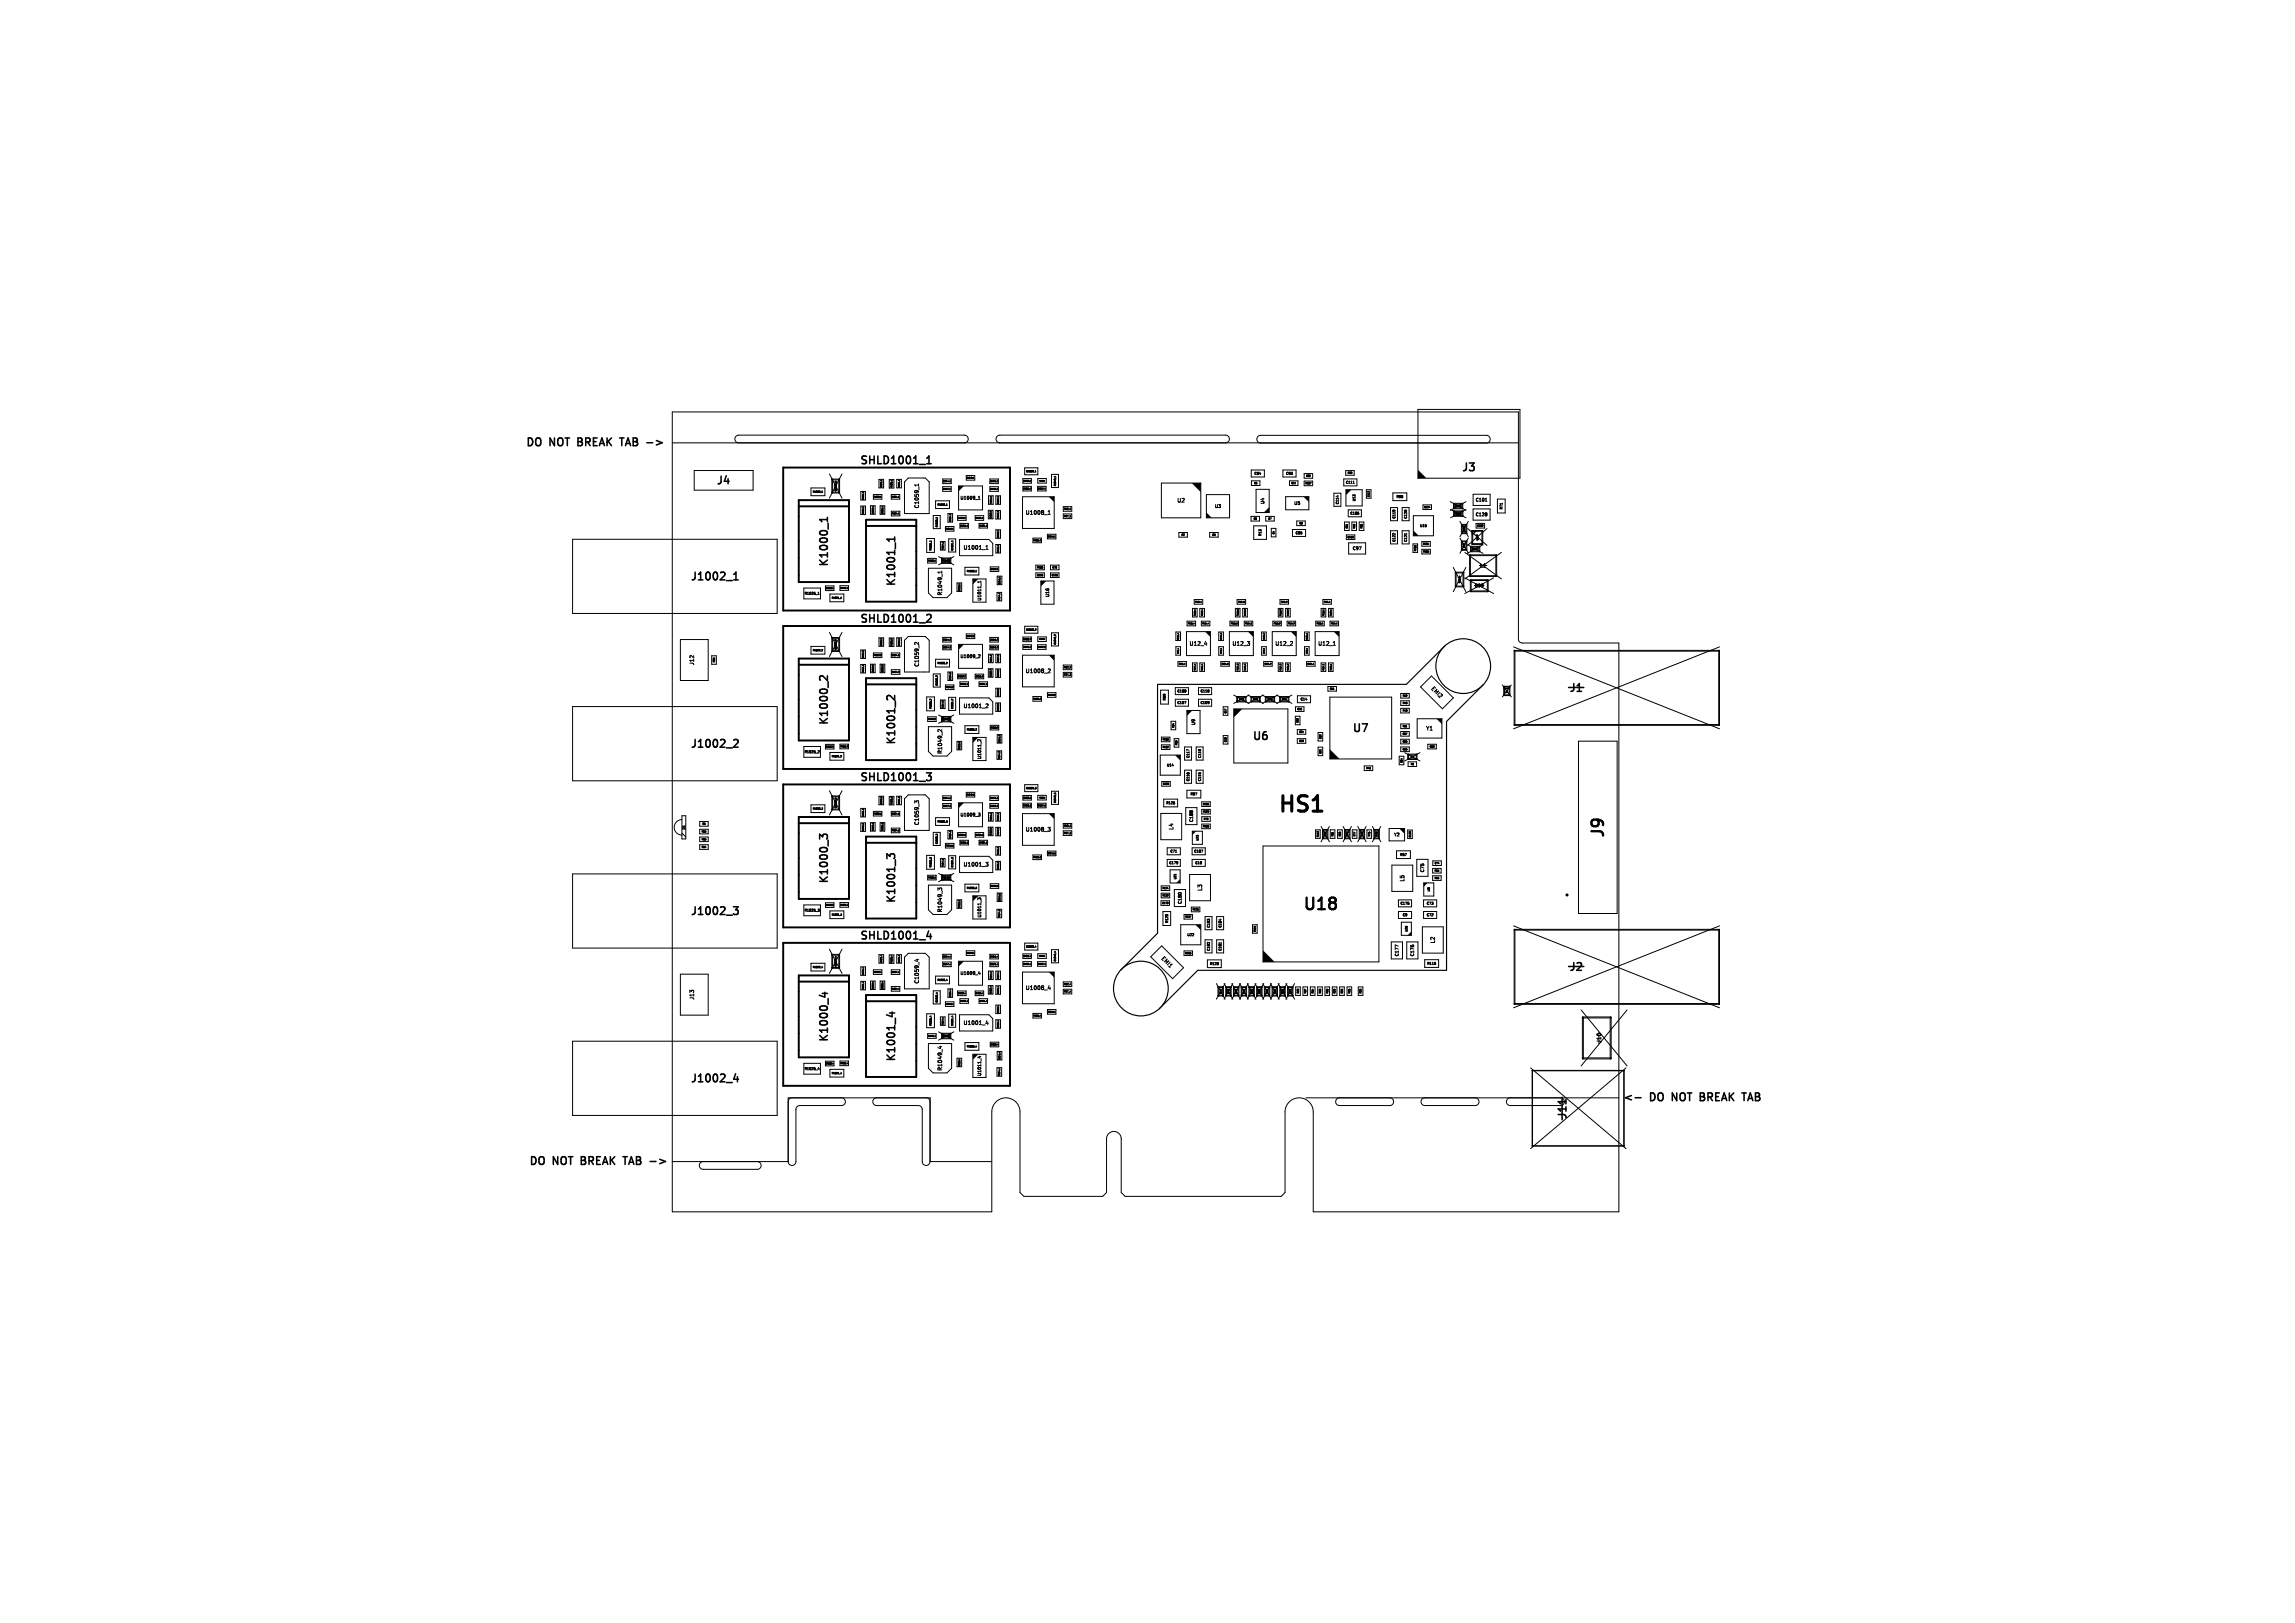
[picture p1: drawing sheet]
<svg xmlns="http://www.w3.org/2000/svg" width="297mm" height="210mm" viewBox="0 0 297 210" stroke-linecap="round" stroke-linejoin="round" font-family="sans-serif">
<defs><g id="words">
<text font-size="2.8" x="165.1" y="105.7">HS1</text>
<g font-size="2.1">
<text x="208" y="108.6" transform="rotate(-90 208 108.6)">J9</text>
<text x="168.4" y="118.2">U18</text>
</g>
<g font-size="1.4">
<text x="68" y="57.8">DO</text>
<text x="71.2" y="57.8">NOT</text>
<text x="75.2" y="57.8">BREAK TAB -&gt;</text>
<text x="92.6" y="63">J4</text>
<text x="111.2" y="60.4">SHLD1001_1</text>
<text x="189" y="61.3">J3</text>
<text x="89.2" y="75.4">J1002_1</text>
<text x="107.4" y="73.5" transform="rotate(-90 107.4 73.5)">K1000_1</text>
<text x="116.1" y="76" transform="rotate(-90 116.1 76)">K1001_1</text>
<text x="111.2" y="80.9">SHLD1001_2</text>
<text x="202.9" y="89.8">J1</text>
<text x="107.4" y="94" transform="rotate(-90 107.4 94)">K1000_2</text>
<text x="174.9" y="95">U7</text>
<text x="89.2" y="97">J1002_2</text>
<text x="111.2" y="101.4">SHLD1001_3</text>
<text x="116.1" y="96.5" transform="rotate(-90 116.1 96.5)">K1001_2</text>
<text x="162" y="96">U6</text>
<text x="89.2" y="118.7">J1002_3</text>
<text x="107.4" y="114.5" transform="rotate(-90 107.4 114.5)">K1000_3</text>
<text x="116.1" y="117" transform="rotate(-90 116.1 117)">K1001_3</text>
<text x="111.2" y="121.9">SHLD1001_4</text>
<text x="202.9" y="125.9">J2</text>
<text x="107.4" y="135" transform="rotate(-90 107.4 135)">K1000_4</text>
<text x="116.1" y="137.5" transform="rotate(-90 116.1 137.5)">K1001_4</text>
<text x="89.2" y="140.3">J1002_4</text>
<text x="210" y="142.6">&lt;-</text>
<text x="213.6" y="142.6">DO</text>
<text x="216.8" y="142.6">NOT</text>
<text x="220.9" y="142.6">BREAK TAB</text>
<text x="203" y="144.9" transform="rotate(-90 203 144.9)">J11</text>
<text x="68.3" y="150.8">DO</text>
<text x="71.5" y="150.8">NOT</text>
<text x="75.5" y="150.8">BREAK TAB -&gt;</text>
</g>
<g font-size=".7">
<text x="119.1" y="65.9" transform="rotate(-90 119.1 65.9)">C1059_1</text>
<text x="152.2" y="65.2">U2</text>
<text x="124.6" y="71.3">U1001_1</text>
<text x="132.6" y="66.7">U1008_1</text>
<text x="122.1" y="77.2" transform="rotate(-90 122.1 77.2)">R1049_1</text>
<text x="191.4" y="73.6">L1</text>
<text x="153.8" y="83.7">U12_4</text>
<text x="159.4" y="83.7">U12_3</text>
<text x="164.9" y="83.7">U12_2</text>
<text x="170.5" y="83.7">U12_1</text>
<text x="90" y="86.2" transform="rotate(-90 90 86.2)">J12</text>
<text x="119.1" y="86.4" transform="rotate(-90 119.1 86.4)">C1059_2</text>
<text x="132.6" y="87.2">U1008_2</text>
<text x="185" y="89.2" transform="rotate(45 185 89.2)">EMI2</text>
<text x="124.6" y="91.8">U1001_2</text>
<text x="184.4" y="94.7">Y1</text>
<text x="122.1" y="97.7" transform="rotate(-90 122.1 97.7)">R1049_2</text>
<text x="119.1" y="106.9" transform="rotate(-90 119.1 106.9)">C1059_3</text>
<text x="132.6" y="107.7">U1008_3</text>
<text x="152" y="107.5" transform="rotate(-90 152 107.5)">L4</text>
<text x="124.6" y="112.3">U1001_3</text>
<text x="122.1" y="118.2" transform="rotate(-90 122.1 118.2)">R1049_3</text>
<text x="155.7" y="115.4" transform="rotate(-90 155.7 115.4)">L3</text>
<text x="181.9" y="114.2" transform="rotate(-90 181.9 114.2)">L5</text>
<text x="150.1" y="124.1" transform="rotate(45 150.1 124.1)">EMI1</text>
<text x="185.8" y="122.2" transform="rotate(-90 185.8 122.2)">L2</text>
<text x="90" y="129.5" transform="rotate(-90 90 129.5)">J13</text>
<text x="119.1" y="127.4" transform="rotate(-90 119.1 127.4)">C1059_4</text>
<text x="132.6" y="128.2">U1008_4</text>
<text x="124.6" y="132.8">U1001_4</text>
<text x="207.3" y="135.1" transform="rotate(-90 207.3 135.1)">J10</text>
<text x="122.1" y="138.7" transform="rotate(-90 122.1 138.7)">R1049_4</text>
</g>
<g font-size=".6">
<text x="124.2" y="64.7">U1009_1</text>
<text x="157.1" y="65.8">U3</text>
<text x="163.7" y="65.3" transform="rotate(-90 163.7 65.3)">U4</text>
<text x="167.4" y="65.4">U5</text>
<text x="190.9" y="65">C101</text>
<text x="175" y="71.3">C97</text>
<text x="190.9" y="66.9">C128</text>
<text x="127.1" y="77.8" transform="rotate(-90 127.1 77.8)">U1011_1</text>
<text x="135.9" y="77.3" transform="rotate(-90 135.9 77.3)">U16</text>
<text x="190.8" y="76.1">C99</text>
<text x="124.2" y="85.2">U1009_2</text>
<text x="154.8" y="93.9" transform="rotate(-90 154.8 93.9)">U9</text>
<text x="127.1" y="98.3" transform="rotate(-90 127.1 98.3)">U1011_2</text>
<text x="124.2" y="105.7">U1009_3</text>
<text x="154.5" y="106.5" transform="rotate(-90 154.5 106.5)">C188</text>
<text x="180.3" y="108.3">Y2</text>
<text x="184.4" y="113" transform="rotate(-90 184.4 113)">C75</text>
<text x="127.1" y="118.8" transform="rotate(-90 127.1 118.8)">U1011_3</text>
<text x="153" y="117.1" transform="rotate(-90 153 117.1)">C180</text>
<text x="181.1" y="123.8" transform="rotate(-90 181.1 123.8)">C177</text>
<text x="183.1" y="123.8" transform="rotate(-90 183.1 123.8)">C176</text>
<text x="124.2" y="126.2">U1009_4</text>
<text x="127.1" y="139.3" transform="rotate(-90 127.1 139.3)">U1011_4</text>
</g>
<g font-size=".4">
<text x="162.3" y="61.5">C94</text>
<text x="166.4" y="61.5">C93</text>
<text x="173.3" y="65.3" transform="rotate(-90 173.3 65.3)">C114</text>
<text x="174.1" y="62.7">C111</text>
<text x="175.5" y="64.9" transform="rotate(-90 175.5 64.9)">U13</text>
<text x="180.7" y="64.5">R98</text>
<text x="194.5" y="66" transform="rotate(-90 194.5 66)">R71</text>
<text x="163.3" y="69.4" transform="rotate(-90 163.3 69.4)">R13</text>
<text x="167.6" y="69.2">C85</text>
<text x="174.7" y="66.7">C106</text>
<text x="180.6" y="70.2" transform="rotate(-90 180.6 70.2)">C122</text>
<text x="180.6" y="67.2" transform="rotate(-90 180.6 67.2)">C119</text>
<text x="182.1" y="70.2" transform="rotate(-90 182.1 70.2)">C121</text>
<text x="182.1" y="67.2" transform="rotate(-90 182.1 67.2)">C120</text>
<text x="183.7" y="68.3">U15</text>
<text x="104.1" y="77">R1025_1</text>
<text x="189.1" y="75.5" transform="rotate(-90 189.1 75.5)">R14</text>
<text x="152.3" y="89.7">C108</text>
<text x="155.3" y="89.7">C110</text>
<text x="150.9" y="90.7" transform="rotate(-90 150.9 90.7)">R89</text>
<text x="152.3" y="91.2">C107</text>
<text x="155.3" y="91.2">C109</text>
<text x="168.3" y="90.7">C14</text>
<text x="104.1" y="97.5">R1025_2</text>
<text x="150.9" y="99.2">U14</text>
<text x="154" y="101.1" transform="rotate(-90 154 101.1)">C116</text>
<text x="154" y="98.1" transform="rotate(-90 154 98.1)">C117</text>
<text x="155.5" y="101.1" transform="rotate(-90 155.5 101.1)">C115</text>
<text x="155.5" y="98.1" transform="rotate(-90 155.5 98.1)">C118</text>
<text x="88.7" y="107.4" transform="rotate(-90 88.7 107.4)">D1</text>
<text x="150.9" y="104.1">R126</text>
<text x="154" y="103">R97</text>
<text x="151.3" y="111.9">C179</text>
<text x="151.4" y="110.4">C71</text>
<text x="154.5" y="110.4">C187</text>
<text x="154.6" y="111.9">C10</text>
<text x="181.1" y="110.8">R57</text>
<text x="104.1" y="118">R1025_3</text>
<text x="151.2" y="119.5" transform="rotate(-90 151.2 119.5)">R120</text>
<text x="181.2" y="117.1">C175</text>
<text x="181.5" y="118.6">C9</text>
<text x="184.6" y="117.1">C73</text>
<text x="184.6" y="118.6">C72</text>
<text x="153.6" y="121.2">U22</text>
<text x="156.5" y="124.9">R123</text>
<text x="156.6" y="123.1" transform="rotate(-90 156.6 123.1)">C182</text>
<text x="156.6" y="120.1" transform="rotate(-90 156.6 120.1)">C183</text>
<text x="158.1" y="123.1" transform="rotate(-90 158.1 123.1)">C181</text>
<text x="158.1" y="120.1" transform="rotate(-90 158.1 120.1)">C184</text>
<text x="184.6" y="124.9">R116</text>
<text x="104.1" y="138.5">R1025_4</text>
</g>
<g font-size=".3">
<text x="105.2" y="63.8">R1022_1</text>
<text x="108.3" y="63.6" transform="rotate(-90 108.3 63.6)">C1022_1</text>
<text x="121.3" y="65.5">R1038_1</text>
<text x="132.8" y="61.1">C1039_1</text>
<text x="136.7" y="62.9" transform="rotate(-90 136.7 62.9)">C1040_1</text>
<text x="162.3" y="62.7">C5</text>
<text x="167.1" y="62.7">C11</text>
<text x="168.9" y="62.7">R107</text>
<text x="169" y="61.7">C82</text>
<text x="174.4" y="61.4">R90</text>
<text x="177.3" y="64.3" transform="rotate(-90 177.3 64.3)">C112</text>
<text x="184.3" y="65.8">C124</text>
<text x="188.3" y="65.6">C100</text>
<text x="120.6" y="71.3" transform="rotate(-90 120.6 71.3)">R1035_1</text>
<text x="121.4" y="68.2" transform="rotate(-90 121.4 68.2)">C1030_1</text>
<text x="123.4" y="71.3" transform="rotate(-90 123.4 71.3)">C1031_1</text>
<text x="137.6" y="67">R97_1</text>
<text x="137.6" y="66">R52_1</text>
<text x="152.9" y="69.4">C2</text>
<text x="156.9" y="69.4">C3</text>
<text x="162.2" y="67.3">C6</text>
<text x="164.1" y="67.3">C7</text>
<text x="165" y="69.2" transform="rotate(-90 165 69.2)">C4</text>
<text x="168.1" y="67.9">C8</text>
<text x="174.4" y="69.7">C103</text>
<text x="174.5" y="68.4" transform="rotate(-90 174.5 68.4)">R91</text>
<text x="175.4" y="68.4" transform="rotate(-90 175.4 68.4)">R93</text>
<text x="176.4" y="68.4" transform="rotate(-90 176.4 68.4)">R96</text>
<text x="183.3" y="71.4" transform="rotate(-90 183.3 71.4)">R100</text>
<text x="184.1" y="70.5">R104</text>
<text x="184.1" y="71.5">R105</text>
<text x="188.3" y="66.6">R109</text>
<text x="189.6" y="70.9" transform="rotate(-90 189.6 70.9)">R72</text>
<text x="189.6" y="68.9" transform="rotate(-90 189.6 68.9)">R110</text>
<text x="190.5" y="71.2">C127</text>
<text x="191.2" y="68.2">C102</text>
<text x="191.4" y="70" transform="rotate(-90 191.4 70)">U17</text>
<text x="107.6" y="77.5">R1021_1</text>
<text x="125.1" y="74.1">R1003_1</text>
<text x="134.2" y="74.6">C125</text>
<text x="134.2" y="73.6">R106</text>
<text x="136.1" y="74.6">C126</text>
<text x="136.2" y="73.6">C76</text>
<text x="132.8" y="81.6">C1039_2</text>
<text x="136.7" y="83.4" transform="rotate(-90 136.7 83.4)">C1040_2</text>
<text x="92.6" y="85.7" transform="rotate(-90 92.6 85.7)">R83</text>
<text x="105.2" y="84.3">R1022_2</text>
<text x="108.3" y="84.1" transform="rotate(-90 108.3 84.1)">C1022_2</text>
<text x="121.3" y="86">R1038_2</text>
<text x="121.4" y="88.7" transform="rotate(-90 121.4 88.7)">C1030_2</text>
<text x="137.6" y="86.5">R52_2</text>
<text x="137.6" y="87.5">R97_2</text>
<text x="172.1" y="89.3">C51</text>
<text x="120.6" y="91.8" transform="rotate(-90 120.6 91.8)">R1035_2</text>
<text x="123.4" y="91.8" transform="rotate(-90 123.4 91.8)">C1031_2</text>
<text x="125.1" y="94.6">R1003_2</text>
<text x="150.4" y="95.8">R103</text>
<text x="152" y="94.2" transform="rotate(-90 152 94.2)">R94</text>
<text x="158.8" y="92.3" transform="rotate(-90 158.8 92.3)">C17</text>
<text x="160.3" y="90.6">R18</text>
<text x="162.2" y="90.6">R19</text>
<text x="164" y="90.6">R20</text>
<text x="165.9" y="90.6">R21</text>
<text x="167.9" y="91.9">C16</text>
<text x="168.1" y="93.6" transform="rotate(-90 168.1 93.6)">R22</text>
<text x="168.1" y="94.9">C24</text>
<text x="171" y="95.7" transform="rotate(-90 171 95.7)">C62</text>
<text x="181.5" y="94.1">R51</text>
<text x="181.5" y="95.1">C67</text>
<text x="181.5" y="91.1">R49</text>
<text x="181.5" y="92.1">R48</text>
<text x="181.5" y="90.2">R52</text>
<text x="107.6" y="98">R1021_2</text>
<text x="150.4" y="96.8">R102</text>
<text x="150.5" y="101.6">C123</text>
<text x="152.4" y="96.5" transform="rotate(-90 152.4 96.5)">R99</text>
<text x="158.8" y="96.1" transform="rotate(-90 158.8 96.1)">C18</text>
<text x="168.1" y="96">C19</text>
<text x="171" y="97.6" transform="rotate(-90 171 97.6)">C91</text>
<text x="176.8" y="99.6">R43</text>
<text x="181.5" y="96.1">C66</text>
<text x="181.5" y="97.1">C65</text>
<text x="181.5" y="98.7" transform="rotate(-90 181.5 98.7)">C64</text>
<text x="182.5" y="98.1">R4</text>
<text x="182.5" y="99">R5</text>
<text x="185" y="96.8">C68</text>
<text x="90.8" y="107.8">R65</text>
<text x="90.9" y="106.8">R6</text>
<text x="105.2" y="104.8">R1022_3</text>
<text x="108.3" y="104.6" transform="rotate(-90 108.3 104.6)">C1022_3</text>
<text x="121.3" y="106.5">R1038_3</text>
<text x="132.8" y="102.1">C1039_3</text>
<text x="136.7" y="103.9" transform="rotate(-90 136.7 103.9)">C1040_3</text>
<text x="137.6" y="108">R97_3</text>
<text x="137.6" y="107">R52_3</text>
<text x="155.7" y="105.2">R129</text>
<text x="155.7" y="104.2">C186</text>
<text x="155.7" y="107.1">R130</text>
<text x="155.7" y="106.1">R70</text>
<text x="90.8" y="108.8">R85</text>
<text x="90.8" y="109.8">R64</text>
<text x="120.6" y="112.3" transform="rotate(-90 120.6 112.3)">R1035_3</text>
<text x="121.4" y="109.2" transform="rotate(-90 121.4 109.2)">C1030_3</text>
<text x="123.4" y="112.3" transform="rotate(-90 123.4 112.3)">C1031_3</text>
<text x="152.3" y="113.8" transform="rotate(-90 152.3 113.8)">U21</text>
<text x="155.2" y="108.8" transform="rotate(-90 155.2 108.8)">U23</text>
<text x="170.7" y="108.4" transform="rotate(-90 170.7 108.4)">R112</text>
<text x="171.7" y="108.3" transform="rotate(-90 171.7 108.3)">R82</text>
<text x="172.6" y="108.3" transform="rotate(-90 172.6 108.3)">R81</text>
<text x="173.6" y="108.3" transform="rotate(-90 173.6 108.3)">R80</text>
<text x="174.5" y="108.3" transform="rotate(-90 174.5 108.3)">R79</text>
<text x="175.5" y="108.3" transform="rotate(-90 175.5 108.3)">R77</text>
<text x="176.4" y="108.3" transform="rotate(-90 176.4 108.3)">R78</text>
<text x="177.4" y="108.3" transform="rotate(-90 177.4 108.3)">R76</text>
<text x="178.3" y="108.3" transform="rotate(-90 178.3 108.3)">R75</text>
<text x="182.6" y="108.4" transform="rotate(-90 182.6 108.4)">C130</text>
<text x="185.6" y="112.8">R55</text>
<text x="185.6" y="113.8">R56</text>
<text x="185.6" y="111.9">C74</text>
<text x="107.6" y="118.5">R1021_3</text>
<text x="125.1" y="115.1">R1003_3</text>
<text x="150.4" y="117">C178</text>
<text x="150.4" y="116">R122</text>
<text x="150.4" y="115.1">R124</text>
<text x="153.4" y="118.8">R127</text>
<text x="154.3" y="117.8">R125</text>
<text x="185.1" y="115.4" transform="rotate(-90 185.1 115.4)">U8</text>
<text x="105.2" y="125.3">R1022_4</text>
<text x="108.3" y="125.1" transform="rotate(-90 108.3 125.1)">C1022_4</text>
<text x="132.8" y="122.6">C1039_4</text>
<text x="136.7" y="124.4" transform="rotate(-90 136.7 124.4)">C1040_4</text>
<text x="153.4" y="123.5">C185</text>
<text x="162.6" y="120.6" transform="rotate(-90 162.6 120.6)">R115</text>
<text x="182.2" y="120.6" transform="rotate(-90 182.2 120.6)">U20</text>
<text x="121.3" y="127">R1038_4</text>
<text x="121.4" y="129.7" transform="rotate(-90 121.4 129.7)">C1030_4</text>
<text x="137.6" y="127.5">R52_4</text>
<text x="137.6" y="128.5">R97_4</text>
<text x="158.1" y="128.6" transform="rotate(-90 158.1 128.6)">C47</text>
<text x="159.1" y="128.6" transform="rotate(-90 159.1 128.6)">C46</text>
<text x="160.1" y="128.6" transform="rotate(-90 160.1 128.6)">C43</text>
<text x="161.1" y="128.6" transform="rotate(-90 161.1 128.6)">C42</text>
<text x="162.1" y="128.6" transform="rotate(-90 162.1 128.6)">C39</text>
<text x="163.1" y="128.6" transform="rotate(-90 163.1 128.6)">C38</text>
<text x="164.1" y="128.6" transform="rotate(-90 164.1 128.6)">C35</text>
<text x="165.1" y="128.6" transform="rotate(-90 165.1 128.6)">C34</text>
<text x="166.1" y="128.6" transform="rotate(-90 166.1 128.6)">C31</text>
<text x="167.1" y="128.6" transform="rotate(-90 167.1 128.6)">C30</text>
<text x="168.1" y="128.6" transform="rotate(-90 168.1 128.6)">R38</text>
<text x="169.1" y="128.6" transform="rotate(-90 169.1 128.6)">R37</text>
<text x="170" y="128.6" transform="rotate(-90 170 128.6)">R34</text>
<text x="171" y="128.6" transform="rotate(-90 171 128.6)">R33</text>
<text x="171.9" y="128.6" transform="rotate(-90 171.9 128.6)">R30</text>
<text x="172.9" y="128.6" transform="rotate(-90 172.9 128.6)">R29</text>
<text x="173.8" y="128.6" transform="rotate(-90 173.8 128.6)">R26</text>
<text x="174.8" y="128.6" transform="rotate(-90 174.8 128.6)">R25</text>
<text x="176.2" y="128.6" transform="rotate(-90 176.2 128.6)">R23</text>
<text x="120.6" y="132.8" transform="rotate(-90 120.6 132.8)">R1035_4</text>
<text x="123.4" y="132.8" transform="rotate(-90 123.4 132.8)">C1031_4</text>
<text x="125.1" y="135.6">R1003_4</text>
<text x="107.6" y="139">R1021_4</text>
</g>
<g font-size=".2">
<text x="111.8" y="64.7" transform="rotate(-90 111.8 64.7)">C1011_1</text>
<text x="113.1" y="64.4">R1002_1</text>
<text x="114.2" y="63.1" transform="rotate(-90 114.2 63.1)">C1025_1</text>
<text x="115.4" y="64.4">C1024_1</text>
<text x="115.5" y="63.1" transform="rotate(-90 115.5 63.1)">R1026_1</text>
<text x="116.5" y="63.1" transform="rotate(-90 116.5 63.1)">C1021_1</text>
<text x="122" y="62.4">C1044_1</text>
<text x="122" y="63.4">C1047_1</text>
<text x="125.1" y="61.9">C1048_1</text>
<text x="128.1" y="62.4">C1046_1</text>
<text x="128.1" y="63.4">C1049_1</text>
<text x="128.3" y="65.2" transform="rotate(-90 128.3 65.2)">R1041_1</text>
<text x="129.3" y="65.2" transform="rotate(-90 129.3 65.2)">R1037_1</text>
<text x="132.4" y="62.3">C1038_1</text>
<text x="132.4" y="63.3">C1036_1</text>
<text x="134.3" y="63.3">C1037_1</text>
<text x="111.8" y="66.5" transform="rotate(-90 111.8 66.5)">R1001_1</text>
<text x="113.1" y="66.5" transform="rotate(-90 113.1 66.5)">C1012_1</text>
<text x="114.3" y="66.5" transform="rotate(-90 114.3 66.5)">C1023_1</text>
<text x="115.4" y="66.6">R1024_1</text>
<text x="122.1" y="71.1" transform="rotate(-90 122.1 71.1)">R1047_1</text>
<text x="122.4" y="68.5">R1043_1</text>
<text x="123.1" y="67.5" transform="rotate(-90 123.1 67.5)">C1034_1</text>
<text x="124" y="67.1">C1052_1</text>
<text x="124.3" y="68.1">C1055_1</text>
<text x="126.2" y="67.1">C1056_1</text>
<text x="126.7" y="68.1">C1001_1</text>
<text x="128.3" y="67.1" transform="rotate(-90 128.3 67.1)">C1032_1</text>
<text x="129.3" y="71.5" transform="rotate(-90 129.3 71.5)">C1035_1</text>
<text x="129.3" y="69.6" transform="rotate(-90 129.3 69.6)">C1002_1</text>
<text x="129.3" y="67.1" transform="rotate(-90 129.3 67.1)">R1042_1</text>
<text x="133.7" y="70">R1033_1</text>
<text x="135.6" y="69.5">C1043_1</text>
<text x="106.9" y="76.2">C1058_1</text>
<text x="108.7" y="76.2">R1053_1</text>
<text x="120.1" y="72.7">R1039_1</text>
<text x="121.9" y="72.7">R1048_1</text>
<text x="124.3" y="76.5" transform="rotate(-90 124.3 76.5)">C1053_1</text>
<text x="128.2" y="73.8">C1050_1</text>
<text x="129.4" y="77.7" transform="rotate(-90 129.4 77.7)">R1044_1</text>
<text x="129.5" y="75.6" transform="rotate(-90 129.5 75.6)">C1045_1</text>
<text x="154.6" y="78">R131_4</text>
<text x="160.2" y="78">R131_3</text>
<text x="165.7" y="78">R131_2</text>
<text x="171.3" y="78">R131_1</text>
<text x="114.2" y="83.6" transform="rotate(-90 114.2 83.6)">C1025_2</text>
<text x="115.5" y="83.6" transform="rotate(-90 115.5 83.6)">R1026_2</text>
<text x="116.5" y="83.6" transform="rotate(-90 116.5 83.6)">C1021_2</text>
<text x="122" y="82.9">C1044_2</text>
<text x="122" y="83.9">C1047_2</text>
<text x="125.1" y="82.4">C1048_2</text>
<text x="128.1" y="83.9">C1049_2</text>
<text x="128.1" y="82.9">C1046_2</text>
<text x="132.4" y="82.8">C1038_2</text>
<text x="132.4" y="83.8">C1036_2</text>
<text x="134.3" y="83.8">C1037_2</text>
<text x="152.6" y="82.8" transform="rotate(-90 152.6 82.8)">C105_4</text>
<text x="153.7" y="80.8">R135_4</text>
<text x="154.7" y="79.7" transform="rotate(-90 154.7 79.7)">R133_4</text>
<text x="155.6" y="80.8">R134_4</text>
<text x="155.7" y="79.7" transform="rotate(-90 155.7 79.7)">R132_4</text>
<text x="158.1" y="82.8" transform="rotate(-90 158.1 82.8)">C105_3</text>
<text x="159.3" y="80.8">R135_3</text>
<text x="160.3" y="79.7" transform="rotate(-90 160.3 79.7)">R133_3</text>
<text x="161.1" y="80.8">R134_3</text>
<text x="161.2" y="79.7" transform="rotate(-90 161.2 79.7)">R132_3</text>
<text x="163.7" y="82.8" transform="rotate(-90 163.7 82.8)">C105_2</text>
<text x="164.8" y="80.8">R135_2</text>
<text x="165.8" y="79.7" transform="rotate(-90 165.8 79.7)">R133_2</text>
<text x="166.7" y="80.8">R134_2</text>
<text x="166.8" y="79.7" transform="rotate(-90 166.8 79.7)">R132_2</text>
<text x="169.2" y="82.8" transform="rotate(-90 169.2 82.8)">C105_1</text>
<text x="170.4" y="80.8">R135_1</text>
<text x="171.4" y="79.7" transform="rotate(-90 171.4 79.7)">R133_1</text>
<text x="172.2" y="80.8">R134_1</text>
<text x="172.3" y="79.7" transform="rotate(-90 172.3 79.7)">R132_1</text>
<text x="111.8" y="87" transform="rotate(-90 111.8 87)">R1001_2</text>
<text x="111.8" y="85.2" transform="rotate(-90 111.8 85.2)">C1011_2</text>
<text x="113.1" y="84.9">R1002_2</text>
<text x="113.1" y="87" transform="rotate(-90 113.1 87)">C1012_2</text>
<text x="114.3" y="87" transform="rotate(-90 114.3 87)">C1023_2</text>
<text x="115.4" y="84.9">C1024_2</text>
<text x="115.4" y="87.1">R1024_2</text>
<text x="122.4" y="89">R1043_2</text>
<text x="123.1" y="88" transform="rotate(-90 123.1 88)">C1034_2</text>
<text x="124" y="87.6">C1052_2</text>
<text x="124.3" y="88.6">C1055_2</text>
<text x="126.2" y="87.6">C1056_2</text>
<text x="126.7" y="88.6">C1001_2</text>
<text x="128.3" y="87.6" transform="rotate(-90 128.3 87.6)">C1032_2</text>
<text x="128.3" y="85.7" transform="rotate(-90 128.3 85.7)">R1041_2</text>
<text x="129.3" y="87.6" transform="rotate(-90 129.3 87.6)">R1042_2</text>
<text x="129.3" y="85.7" transform="rotate(-90 129.3 85.7)">R1037_2</text>
<text x="152.5" y="86">C104_4</text>
<text x="152.6" y="84.6" transform="rotate(-90 152.6 84.6)">C70_4</text>
<text x="154.7" y="86.8" transform="rotate(-90 154.7 86.8)">R137_4</text>
<text x="155.7" y="86.8" transform="rotate(-90 155.7 86.8)">R136_4</text>
<text x="158.1" y="86">C104_3</text>
<text x="158.1" y="84.6" transform="rotate(-90 158.1 84.6)">C70_3</text>
<text x="160.3" y="86.8" transform="rotate(-90 160.3 86.8)">R137_3</text>
<text x="161.2" y="86.8" transform="rotate(-90 161.2 86.8)">R136_3</text>
<text x="163.6" y="86">C104_2</text>
<text x="163.7" y="84.6" transform="rotate(-90 163.7 84.6)">C70_2</text>
<text x="165.8" y="86.8" transform="rotate(-90 165.8 86.8)">R137_2</text>
<text x="166.8" y="86.8" transform="rotate(-90 166.8 86.8)">R136_2</text>
<text x="169.2" y="86">C104_1</text>
<text x="169.2" y="84.6" transform="rotate(-90 169.2 84.6)">C70_1</text>
<text x="171.4" y="86.8" transform="rotate(-90 171.4 86.8)">R137_1</text>
<text x="172.3" y="86.8" transform="rotate(-90 172.3 86.8)">R136_1</text>
<text x="195.1" y="89.7" transform="rotate(-90 195.1 89.7)">D2</text>
<text x="120.1" y="93.2">R1039_2</text>
<text x="121.9" y="93.2">R1048_2</text>
<text x="122.1" y="91.6" transform="rotate(-90 122.1 91.6)">R1047_2</text>
<text x="128.2" y="94.3">C1050_2</text>
<text x="129.3" y="92" transform="rotate(-90 129.3 92)">C1035_2</text>
<text x="129.3" y="90.1" transform="rotate(-90 129.3 90.1)">C1002_2</text>
<text x="133.7" y="90.5">R1033_2</text>
<text x="135.6" y="90">C1043_2</text>
<text x="106.9" y="96.7">C1058_2</text>
<text x="108.7" y="96.7">R1053_2</text>
<text x="124.3" y="97" transform="rotate(-90 124.3 97)">C1053_2</text>
<text x="129.4" y="98.2" transform="rotate(-90 129.4 98.2)">R1044_2</text>
<text x="129.5" y="96.1" transform="rotate(-90 129.5 96.1)">C1045_2</text>
<text x="111.8" y="107.5" transform="rotate(-90 111.8 107.5)">R1001_3</text>
<text x="111.8" y="105.7" transform="rotate(-90 111.8 105.7)">C1011_3</text>
<text x="113.1" y="105.4">R1002_3</text>
<text x="113.1" y="107.5" transform="rotate(-90 113.1 107.5)">C1012_3</text>
<text x="114.2" y="104.1" transform="rotate(-90 114.2 104.1)">C1025_3</text>
<text x="114.3" y="107.5" transform="rotate(-90 114.3 107.5)">C1023_3</text>
<text x="115.4" y="105.4">C1024_3</text>
<text x="115.4" y="107.6">R1024_3</text>
<text x="115.5" y="104.1" transform="rotate(-90 115.5 104.1)">R1026_3</text>
<text x="116.5" y="104.1" transform="rotate(-90 116.5 104.1)">C1021_3</text>
<text x="122" y="104.4">C1047_3</text>
<text x="122" y="103.4">C1044_3</text>
<text x="125.1" y="102.9">C1048_3</text>
<text x="128.1" y="104.4">C1049_3</text>
<text x="128.1" y="103.4">C1046_3</text>
<text x="128.3" y="106.2" transform="rotate(-90 128.3 106.2)">R1041_3</text>
<text x="129.3" y="106.2" transform="rotate(-90 129.3 106.2)">R1037_3</text>
<text x="132.4" y="103.3">C1038_3</text>
<text x="132.4" y="104.3">C1036_3</text>
<text x="134.3" y="104.3">C1037_3</text>
<text x="120.1" y="113.7">R1039_3</text>
<text x="121.9" y="113.7">R1048_3</text>
<text x="122.1" y="112.1" transform="rotate(-90 122.1 112.1)">R1047_3</text>
<text x="122.4" y="109.5">R1043_3</text>
<text x="123.1" y="108.5" transform="rotate(-90 123.1 108.5)">C1034_3</text>
<text x="124" y="108.1">C1052_3</text>
<text x="124.3" y="109.1">C1055_3</text>
<text x="126.2" y="108.1">C1056_3</text>
<text x="126.7" y="109.1">C1001_3</text>
<text x="128.3" y="108.1" transform="rotate(-90 128.3 108.1)">C1032_3</text>
<text x="129.3" y="112.5" transform="rotate(-90 129.3 112.5)">C1035_3</text>
<text x="129.3" y="110.6" transform="rotate(-90 129.3 110.6)">C1002_3</text>
<text x="129.3" y="108.1" transform="rotate(-90 129.3 108.1)">R1042_3</text>
<text x="133.7" y="111">R1033_3</text>
<text x="135.6" y="110.5">C1043_3</text>
<text x="106.9" y="117.2">C1058_3</text>
<text x="108.7" y="117.2">R1053_3</text>
<text x="124.3" y="117.5" transform="rotate(-90 124.3 117.5)">C1053_3</text>
<text x="128.2" y="114.8">C1050_3</text>
<text x="129.4" y="118.7" transform="rotate(-90 129.4 118.7)">R1044_3</text>
<text x="129.5" y="116.6" transform="rotate(-90 129.5 116.6)">C1045_3</text>
<text x="113.1" y="125.9">R1002_4</text>
<text x="114.2" y="124.6" transform="rotate(-90 114.2 124.6)">C1025_4</text>
<text x="115.4" y="125.9">C1024_4</text>
<text x="115.5" y="124.6" transform="rotate(-90 115.5 124.6)">R1026_4</text>
<text x="116.5" y="124.6" transform="rotate(-90 116.5 124.6)">C1021_4</text>
<text x="122" y="123.9">C1044_4</text>
<text x="122" y="124.9">C1047_4</text>
<text x="125.1" y="123.4">C1048_4</text>
<text x="128.1" y="123.9">C1046_4</text>
<text x="128.1" y="124.9">C1049_4</text>
<text x="132.4" y="123.8">C1038_4</text>
<text x="132.4" y="124.8">C1036_4</text>
<text x="134.3" y="124.8">C1037_4</text>
<text x="111.8" y="128" transform="rotate(-90 111.8 128)">R1001_4</text>
<text x="111.8" y="126.2" transform="rotate(-90 111.8 126.2)">C1011_4</text>
<text x="113.1" y="128" transform="rotate(-90 113.1 128)">C1012_4</text>
<text x="114.3" y="128" transform="rotate(-90 114.3 128)">C1023_4</text>
<text x="115.4" y="128.1">R1024_4</text>
<text x="122.4" y="130">R1043_4</text>
<text x="123.1" y="129" transform="rotate(-90 123.1 129)">C1034_4</text>
<text x="124" y="128.6">C1052_4</text>
<text x="124.3" y="129.6">C1055_4</text>
<text x="126.2" y="128.6">C1056_4</text>
<text x="126.7" y="129.6">C1001_4</text>
<text x="128.3" y="128.6" transform="rotate(-90 128.3 128.6)">C1032_4</text>
<text x="128.3" y="126.7" transform="rotate(-90 128.3 126.7)">R1041_4</text>
<text x="129.3" y="131.1" transform="rotate(-90 129.3 131.1)">C1002_4</text>
<text x="129.3" y="128.6" transform="rotate(-90 129.3 128.6)">R1042_4</text>
<text x="129.3" y="126.7" transform="rotate(-90 129.3 126.7)">R1037_4</text>
<text x="133.7" y="131.5">R1033_4</text>
<text x="135.6" y="131">C1043_4</text>
<text x="106.9" y="137.7">C1058_4</text>
<text x="108.7" y="137.7">R1053_4</text>
<text x="120.1" y="134.2">R1039_4</text>
<text x="121.9" y="134.2">R1048_4</text>
<text x="122.1" y="132.6" transform="rotate(-90 122.1 132.6)">R1047_4</text>
<text x="124.3" y="138" transform="rotate(-90 124.3 138)">C1053_4</text>
<text x="128.2" y="135.3">C1050_4</text>
<text x="129.3" y="133" transform="rotate(-90 129.3 133)">C1035_4</text>
<text x="129.5" y="137.1" transform="rotate(-90 129.5 137.1)">C1045_4</text>
<text x="129.4" y="139.2" transform="rotate(-90 129.4 139.2)">R1044_4</text>
</g>
</g></defs>
<g fill="none" stroke="#000" stroke-width=".13">
<path d="M87 53.3h109.5v29.4a.5 .5 0 0 0 .5 .5h12.5v73.6h-39.5v-12.9a1.82 1.82 0 0 0-1.9-1.8 1.82 1.82 0 0 0-1.8 1.8v10.4l-.5 .5h-20.2l-.5-.5v-6.9a.95 .95 0 0 0-.9-1 .95 .95 0 0 0-1 1v6.9l-.5 .5h-10.2l-.5-.5v-10.4a1.82 1.82 0 0 0-1.8-1.8 1.82 1.82 0 0 0-1.8 1.8v12.9h-41.4zM87 57.3h109.5M95.6 57.3a.5 .5 0 0 1-.5-.5 .5 .5 0 0 1 .5-.5h29.2a.5 .5 0 0 1 .5 .5 .5 .5 0 0 1-.5 .5M129.4 57.3a.5 .5 0 0 1-.5-.5 .5 .5 0 0 1 .5-.5h29.2a.5 .5 0 0 1 .5 .5 .5 .5 0 0 1-.5 .5M162.8 56.5l.4-.2h29.2a.5 .5 0 0 1 .5 .5 .5 .5 0 0 1-.6 .5h-29.1a.5 .5 0 0 1-.5-.3 .5 .5 0 0 1 .1-.5zM183.5 53h13.2v8.9h-13.2zM74.1 69.8h26.5v9.6h-26.5zM89.8 60.9h7.7v2.5h-7.7zM104 76.1h2.2v1.4h-2.2zM105 63.1h1.8v1h-1.8zM105.9 76.7v-.1v.3M105.9 76.9h.1"/>
<path d="M106.4 63.7h.1M106.4 63.6h.1M106.4 63.6v.1M106.8 75.8h1.1v.6h-1.1zM107.3 61.3l1.7 3.2M107.4 76.9h1.8v1h-1.8zM107.7 62h.1l-.1 1.8zM107.7 62h1l-1 .1zM107.7 63.7h1l-1 .1zM107.8 76.2h.1M107.8 76.1h.1M107.8 76.1v.1"/>
<path d="M108.1 62.4h.1M108.2 62.2v1.4M108.2 62.3l-.1 .1M108.2 62.3v.1M108.6 62h.1l-.1 1.8zM108.7 75.8h1.1v.6h-1.1zM108.8 77.5h.1M108.8 77.3h.1M108.8 77.3l.1 .2M109 61.3l-1.7 3.2M109.6 76.2h.1M109.6 76v.1"/>
<path d="M109.7 76v.2M109.7 76h-.1M111.4 65.5h.6v1.1h-.6zM111.4 63.6h.6v1.1h-.6zM111.7 63.8h.1M111.7 65.6v.1M111.8 63.7v.1M111.8 65.6v.1M111.8 63.7l-.1 .1M111.8 65.6h-.1M112.7 65.4h.6v1.1h-.6zM112.9 65.6h.1"/>
<path d="M113 65.5v.1M113 64h1.1v.6h-1.1zM113.8 62h.6v1.1h-.6zM113.9 65.4h.6v1.1h-.6zM114 64.4h.1M114 64.2h.1M114 64.2v.2M114.1 62.1v.1M114.1 62.2h-.1M114.3 65.5v.1M114.3 65.6h-.1M115.1 62.1h.6v1.1h-.6z"/>
<path d="M115.3 62.2h.1M115.3 64h1.1v.6h-1.1zM115.4 66.2h1.1v.6h-1.1zM115.4 62.1v.1M115.4 62.2h-.1M116.1 62h.6v1.1h-.6zM116.3 64.4h.1M116.3 66.5h.1M116.3 64.2h.1M116.3 66.4v.1M116.3 66.4h.1M116.3 64.2v.2"/>
<path d="M116.4 62.2h-.1M116.4 62.1v.1M117.6 61.9h2.2l.5 .5v4.1h-3.2v-4.1zM118.9 62.6v.3M118.9 62.8h-.5l.1 .1M119.9 69.7h1v1.8h-1zM120.1 72.3h1.1v.6h-1.1zM120.2 73.5h3v3.2l-.6 .6h-1.8l-.6-.6zM120.3 70l.1 .1M120.4 70.1h.1M120.5 70h-.2M120.5 70v.1"/>
<path d="M120.8 66.7h.9v1.7h-.9zM121 72.6h.1M121 72.5h.1M121 72.5v.1M121.1 64.8h1.8v1h-1.8zM121.1 67h.2M121.1 67h.1M121.1 67l.1 .1M121.3 66.9v.2M121.5 72l1.9 1.1M121.7 70.1h.6v1.1h-.6zM121.9 72.2h.1l-.1 .7z"/>
<path d="M121.9 72.2l1.2 .1h-1.2zM121.9 72.8l1.2 .1h-1.2zM121.9 73.9v.3M121.9 74h-.5l.1 .2M121.9 70.2h.1M122 72.6h1M122 70.2v.1M122 63h1.1v.6h-1.1zM122 62h1.1v.6h-1.1zM122.1 70.2v.1M122.1 70.2h-.2M122.4 68.1h1.1v.6h-1.1z"/>
<path d="M122.5 65.4h.1M122.5 65.2v.2M122.5 65.2v.1M122.7 66.5h.6v1.1h-.6zM122.8 69.7h.9v1.7h-.9zM122.8 72.6h.1M122.8 72.5h.1M122.9 72.5v.1M122.9 72.5h-.1M122.9 62.3h.1M122.9 63.3h.1M122.9 66.6h.1"/>
<path d="M122.9 62.2l.1 .1M122.9 62.2h.1M122.9 63.2h.1M123 63.2v.1M123 63.2h-.1M123 72.2l.1 .1-.1 .6zM123 66.6h-.1M123 66.5v.1M123.3 68.5h.1M123.3 68.4v.1M123.3 70h-.2l.1 .1M123.3 70v.1"/>
<path d="M123.4 72l-1.9 1.1M123.9 75.4h.6v1.1h-.6zM123.9 66.7h1.1v.6h-1.1zM124.1 62.9h3.1v3.1h-3.1zM124.2 69.8h3.8l.5 .5v1.6h-4.3zM124.2 75.5v.1M124.2 75.6h-.1M124.2 67.7h1.1v.6h-1.1zM124.9 67.1h.1M124.9 67v.1M124.9 73.4h1.8v1h-1.8zM125 61.5h1.1v.6h-1.1z"/>
<path d="M125.2 68.1h.1M125.2 68h.1M125.2 68v.1M125.9 74.9h1.7v3h-1.7zM126 61.9h.1M126 61.8h.1M126 61.7v.2M126 61.7v.1M126.2 66.7h1.1v.6h-1.1zM126.3 74h.1M126.3 73.8v.1M126.3 73.8v.2"/>
<path d="M126.3 73.8h.1M126.6 64.6h.2M126.6 64.3l.1-.1v.4M126.7 67.7h1.1v.6h-1.1zM126.9 75.2v.2M126.9 75.3h-.4l.1 .1M127.1 67.1h.1M127.1 67h.1M127.2 67v.1M127.2 67h-.1M127.6 71.1h.3M127.6 70.7l.1-.1v.5"/>
<path d="M127.6 68.1h.1M127.6 68l.1 .1M127.6 68h.1M127.9 66h.6v1.1h-.6zM127.9 64.2h.6v1.1h-.6zM128.1 63h1.1v.6h-1.1zM128.1 62h1.1v.6h-1.1zM128.1 64.3h.2M128.1 64.3h.1M128.2 73.4h1.1v.6h-1.1zM128.2 66.2h.1M128.2 64.3h.1"/>
<path d="M128.3 66.1v.1M128.3 66.2h-.1M128.3 64.2v.1M128.9 64.2h.6v1.1h-.6zM128.9 68.6h.6v1.1h-.6zM128.9 70.5h.6v1.1h-.6zM128.9 66.1h.6v1.1h-.6zM129 63.2l.1 .1M129 63.3h.1M129 76.7h.6v1.1h-.6zM129 62.3h.1M129 62.2l.1 .1"/>
<path d="M129 62.2h.1M129.1 74.6h.6v1.1h-.6zM129.1 73.7h.1M129.1 73.6v.1M129.1 73.6h.1M129.1 66.2h.1M129.1 70.6h.1M129.1 68.7h.1M129.1 64.3h.1M129.2 64.2v.1M129.2 66.1v.1M129.2 68.6v.1"/>
<path d="M129.2 70.5v.1M129.2 64.3h-.1M129.2 66.2h-.1M129.2 70.6h-.1M129.2 68.7h-.1M129.4 76.7v.1M129.4 76.8h-.1M129.4 74.6v.1M129.4 74.7h-.1M132.3 64.3h4.1v4.1h-4.1zM132.4 61.9h1.1v.6h-1.1zM132.4 62.9h1.1v.6h-1.1z"/>
<path d="M132.6 60.5h1.7v.9h-1.7zM133.3 63.3h.1M133.3 63.2v.1M133.3 62.3h.1M133.3 62.2h.1M133.3 62.2v.1M133.7 69.6h1.1v.6h-1.1zM134 61.1h.1M134 60.9h.1M134 60.9v.2M134.1 73.1h1.1v.6h-1.1zM134.1 74.1h1.1v.6h-1.1z"/>
<path d="M134.3 62.9h1.1v.6h-1.1zM134.3 61.9h1.1v.6h-1.1zM134.5 62.2h.1M134.6 62.2l-.1 .1M134.6 62.2h.1M134.6 70h.1M134.6 69.9h.1M134.6 62.2v.1M134.6 69.9v.1M134.7 62.3h.1M134.7 62.2v.1M134.7 62.2h.1"/>
<path d="M134.7 75.2h1.7v3h-1.7zM134.8 62.2h.1M134.8 62.2v.1M134.8 62.3h.1M134.8 74.3h.1M134.9 62.2h.1M134.9 62.2v.1M134.9 62.3h.1M134.9 73.3h.1M134.9 74.4h.1M134.9 73.4h.1M134.9 74.5h.1"/>
<path d="M134.9 73.5h.1M134.9 73.4v.1M134.9 74.4v.1M135 62.2h.1M135 62.3h.1M135.1 62.3h.1M135.2 62.2h-.1M135.2 62.2v.1M135.2 63.3h.1M135.2 63.2h.1M135.2 63.1v.2M135.2 63.1v.1"/>
<path d="M135.6 69.1h1.1v.6h-1.1zM135.6 66.6h.3M135.6 66.2l.2-.1v.5M136 73.1h1.1v.6h-1.1zM136 74.1h1.1v.6h-1.1zM136.1 61.4h.9v1.7h-.9zM136.5 61.7h.1M136.5 69.5h.1M136.5 69.4v.1M136.6 61.6v.1M136.6 61.7h-.1M136.8 74.3h.1"/>
<path d="M136.8 74.4v.1M136.8 74.5h.1M137.6 65.6h1.1v.6h-1.1zM137.6 66.5h1.1v.6h-1.1zM138.5 66.9h.1M138.5 65.9h.1M138.5 65.8v.1M138.5 66.7v.2M150.3 62.5h5.1v4.5h-5.1zM152.6 68.9h1.1v.6h-1.1zM154.3 78.7h.6v1.1h-.6zM154.5 77.6h1.1v.6h-1.1z"/>
<path d="M154.6 78.9h.1M154.6 78.9v.1M155.3 78.7h.6v1.1h-.6zM155.4 77.9h.1M155.5 77.8v.1M155.5 78.9h.1M155.6 78.9v.1M156.1 64h3v3h-3zM156.5 68.9h1.1v.6h-1.1zM159.9 78.7h.6v1.1h-.6zM160.1 77.6h1.1v.6h-1.1zM160.1 78.9v.1"/>
<path d="M160.2 78.9h-.1M160.2 78.9h.1M160.2 78.9v.1M160.8 78.7h.6v1.1h-.6zM160.9 77.8l.1 .1M161 77.9h.1M161.1 78.9l-.1 .1M161.1 78.9h.1M161.2 78.9h.1M161.2 78.9v.1M161.9 66.8h1.1v.6h-1.1zM161.9 60.8h1.7v.9h-1.7z"/>
<path d="M162 62.2h1.1v.6h-1.1zM162.2 68h1.7v1.8h-1.7zM162.6 63.3h1.7v3h-1.7zM163.8 66.8h1.1v.6h-1.1zM164.5 68.4h.6v1.1h-.6zM165.4 78.7h.6v1.1h-.6zM165.6 78.9v.1M165.6 78.9h.1M165.6 77.6h1.1v.6h-1.1zM165.7 78.9h.1M165.7 78.9l.1 .1v-.1M166 60.8h1.7v.9h-1.7z"/>
<path d="M166.4 78.7h.6v1.1h-.6zM166.4 64.3h3v1.7h-3zM166.5 77.8h.1M166.6 77.8h.1M166.6 77.8l-.1 .1h.1M166.6 78.9v.1M166.6 78.9h.1M166.6 78.9l.1 .1v-.1M166.9 62.2h1.1v.6h-1.1zM167.3 68.5h1.7v.9h-1.7zM167.6 62.6h.1M167.8 67.4h1.1v.6h-1.1z"/>
<path d="M168.8 62.2h1.1v.6h-1.1zM168.8 61.3h1.1v.6h-1.1zM169.5 62.4h.2l-.1 .2M171 78.7h.6v1.1h-.6zM171.2 77.6h1.1v.6h-1.1zM171.3 78.9v.1M171.3 78.9l-.1 .1M171.9 78.7h.6v1.1h-.6zM172.1 77.9h.1M172.1 77.8h.1M172.1 77.8v.1M172.1 78.9h.2"/>
<path d="M172.1 78.9h.1M172.2 78.9v.1M172.3 78.9v.1M172.6 63.8h.9v1.7h-.9zM173.1 64.1v.2M173.9 62h1.7v.9h-1.7zM174 67.5h.6v1.1h-.6zM174.2 60.9h1.1v.6h-1.1zM174.2 63.4h2.1v2.1h-2.1zM174.2 69.2h1.1v.6h-1.1zM174.4 67.8v.2M174.5 66h1.7v.9h-1.7z"/>
<path d="M174.5 70.2h2.2v1.5h-2.2zM175 67.5h.6v1.1h-.6zM175 69.4h.1v.1M175.1 69.5h.1M175.1 62.6h.2M175.1 69.5v.1M175.1 69.6h.1M175.2 62.3v.3M175.8 66.3h.1M175.8 66.4h.1M175.8 66.4v.2M175.9 67.5h.6v1.1h-.6z"/>
<path d="M176.8 63.4h.6v1.1h-.6zM177 63.6h.1M177.1 63.6h-.1M177.1 63.6h.1M177.1 63.6l.1 .1v-.1M180 65.7h.9v1.7h-.9zM180 68.7h.9v1.7h-.9zM180.3 66l-.1 .1M180.3 63.8h1.8v1h-1.8zM180.3 66l.2 .1M180.3 66h.1M180.4 66h.1"/>
<path d="M180.4 66v.1M180.5 69v.2l-.1-.2-.2 .1M181.5 65.7h.9v1.7h-.9zM181.5 68.7h.9v1.7h-.9zM181.8 66h.2M182 69v.2M182 69.1h-.2M182.9 70.4h.6v1.1h-.6zM182.9 66.7h2.6v2.6h-2.6zM183.2 70.6h-.1M183.2 70.6h.1M184 71.1h1.1v.6h-1.1z"/>
<path d="M184 70.1h1.1v.6h-1.1zM184.2 65.3h1.1v.6h-1.1zM184.8 70.4h.1M184.8 71.3h.1M184.9 71.3v.1M184.9 71.4h.1M184.9 71.5h.1M184.9 71.4v.1M184.9 65.7h.2M187.7 64.9l2 1.1M187.7 65.9l2 1.1M188.1 73.4l1.6 3.2"/>
<path d="M188.1 65.1l.1 .1v.6zM188.1 65.1l1.2 .1h-1.1zM188.1 65.7l1.2 .1h-1.1zM188.1 66.1l.1 .1v.6zM188.1 66.1l1.2 .1h-1.1zM188.1 66.7l1.2 .1h-1.1zM188.3 65.5h.8M188.3 66.4h.8M188.4 74.1h1h-1zM188.4 74.1v1.8zM188.4 75.9h1h-1zM188.9 74.5v.9"/>
<path d="M188.9 67.5l1.1 1.9M188.9 69.6l1.1 2M189 65.4v.2M189 66.3v.1M189 66.4l.1 .1M189.1 66.5h-.1M189.1 66.4v.1M189.1 67.9h.1v1.2zM189.1 67.9h.7l-.6 .1zM189.1 69h.7l-.6 .1zM189.1 70l.7 .1h-.6zM189.1 70l.1 .1v1.1z"/>
<path d="M189.1 71.1l.7 .1h-.6zM189.2 65.1l.1 .1v.6zM189.2 66.1l.1 .1v.6zM189.4 74.1v1.8zM189.4 68.1h.1M189.5 68v.9M189.5 70.3v.6M189.6 74.8l3.7 2M189.6 71.5l4.7 3.4M189.7 73.4l-1.6 3.2M189.7 65.9l-2 1.1M189.7 64.9l-2 1.1"/>
<path d="M189.7 67.9h.1v1.2zM189.7 70l.1 .1v1.1zM189.9 70.5l2 1.1M189.9 68.4l2.5 2.2M190 67.5l-1.1 1.9M190 69.6l-1.1 2M190.2 71.8h.1l-.1 2.8zM190.2 71.8h3.5l-3.5 .1zM190.2 74.5h3.5l-3.5 .1zM190.3 75l.1 .1-.1 1.5zM190.3 75l2.3 .1h-2.3zM190.3 76.5h2.3l-2.3 .1z"/>
<path d="M190.3 70.7h.1v.7zM190.3 70.7h1.2l-1.1 .1zM190.3 71.3h1.2l-1.1 .1zM190.5 71h.8M190.5 68.7h1.4h-1.4zM190.5 68.7h.1l-.1 1.7zM190.5 70.4h1.4h-1.4zM190.5 68.7h.5l-.5 .5zM190.6 65.9h2.2v1.4h-2.2zM190.6 64h2.2v1.4h-2.2zM190.8 75.8h1.3M191 67.7h1.1v.6h-1.1z"/>
<path d="M191.1 70.9h.2l-.1 .2M191.2 69.1v.8M191.3 69.3l-.3-.1v.2M191.4 70.7h.1v.7zM191.5 73.2h.9M191.8 68.7h.1l-.1 1.7zM191.9 67.9h.1M191.9 70.5l-2 1.1M191.9 68l-.1 .1h.1M192.2 64.9h.2M192.3 64.5v.4M192.4 66.4h.1"/>
<path d="M192.4 66.5v.2M192.4 66.4v.1M192.4 68.4l-2.5 2.2M192.5 75l.1 .1-.1 1.5zM193.3 74.8l-3.7 2M193.6 71.8h.1l-.1 2.8zM193.8 64.6h1v1.8h-1zM194.3 71.5l-4.7 3.4M194.4 65.1v.2M74.1 91.4h26.5v9.6h-26.5zM88.1 82.8h3.5v5.3h-3.5zM92.1 84.9h.6v1.1h-.6z"/>
<path d="M104 96.6h2.2v1.4h-2.2zM105 83.6h1.8v1h-1.8zM105.9 97.1l.1 .1-.2 .2h.2M106.4 84h.1M106.4 84l.1 .1M106.5 84.1l-.2 .1h.2M106.8 96.3h1.1v.6h-1.1zM107.3 81.8l1.7 3.2M107.4 97.4h1.8v1h-1.8zM107.7 82.5h.1l-.1 1.8zM107.7 82.5h1l-1 .1zM107.7 84.2h1l-1 .1z"/>
<path d="M107.8 96.5h.1M107.8 96.5v.1M107.8 96.6l-.1 .1h.1M107.8 96.6h.1M108.1 82.8v.1M108.1 82.8h.1M108.1 82.8l.1 .1v-.1M108.2 82.7v1.4M108.6 82.5h.1l-.1 1.8zM108.7 96.3h1.1v.6h-1.1zM108.8 97.8h.1M108.9 97.8h.1"/>
<path d="M108.9 97.8l-.1 .2h.1M109 81.8l-1.7 3.2M109.6 96.5h.1M109.7 96.5h.1M109.7 96.5v.1M109.7 96.6l-.1 .1h.1M111.4 86h.6v1.1h-.6zM111.4 84.1h.6v1.1h-.6zM111.6 84.2v.1M111.6 86.1h.1M111.6 84.2h.1M111.7 84.2l.1 .1v-.1"/>
<path d="M111.7 86.1l.1 .1v-.1M112.7 85.9h.6v1.1h-.6zM112.9 86.1h.1M112.9 86v.1M112.9 86h.1M112.9 86l.1 .1v-.1M113 84.5h1.1v.6h-1.1zM113.8 82.5h.6v1.1h-.6zM113.9 85.9h.6v1.1h-.6zM114 82.7h.1M114 82.6v.1M114 82.6h.1"/>
<path d="M114 84.7h.1M114 82.6l.1 .1v-.1M114 84.8l-.1 .1h.1M114 84.7v.1M114.1 86v.1M114.1 86h.1M114.2 86h.1M114.3 86v.1l-.1-.1M115.1 82.6h.6v1.1h-.6zM115.3 82.7h.1M115.3 82.6v.1M115.3 82.6h.1"/>
<path d="M115.3 84.5h1.1v.6h-1.1zM115.3 82.6l.1 .1v-.1M115.4 86.7h1.1v.6h-1.1zM116.1 82.5h.6v1.1h-.6zM116.3 82.7h.1M116.3 82.6v.1M116.3 82.6h.1M116.3 84.7h.1M116.3 82.6l.1 .1v-.1M116.3 86.9h.1M116.3 84.8v.1h.1M116.4 84.7h.1"/>
<path d="M116.4 84.7l-.1 .1M116.4 86.9l-.1 .1h.1M116.4 86.9h.1M117.6 82.4h2.2l.5 .5v4.1h-3.2v-4.1zM118.9 83.1v.3l-.4-.3-.1 .1v.2M119.9 90.2h1v1.8h-1zM120.1 92.8h1.1v.6h-1.1zM120.2 94h3v3.2l-.6 .6h-1.8l-.6-.6zM120.3 90.5v.1M120.3 90.6h.1M120.3 90.5h.1M120.4 90.5h-.1"/>
<path d="M120.4 90.5h.1M120.5 90.5v.1l-.1-.1M120.8 87.2h.9v1.7h-.9zM121 93h.1M121.1 93h.1M121.1 93l-.1 .1h.1M121.1 85.3h1.8v1h-1.8zM121.1 87.5h.1M121.1 87.4v.1M121.2 87.4h.1M121.2 87.4h-.1M121.2 87.4l.1 .2v-.2"/>
<path d="M121.5 92.5l1.9 1.1M121.7 90.6h.6v1.1h-.6zM121.9 92.7h.1l-.1 .7zM121.9 92.7l1.2 .1h-1.2zM121.9 93.3l1.2 .1h-1.2zM121.9 94.4v.3l-.4-.3-.1 .1v.2M121.9 90.7h.1M122 93.1h1M122 82.5h1.1v.6h-1.1zM122 83.5h1.1v.6h-1.1zM122.1 90.7v.1l-.2-.1M122.4 88.6h1.1v.6h-1.1z"/>
<path d="M122.5 85.7h.1M122.6 85.7h.1M122.6 85.7v.1M122.6 85.8l-.1 .1h.1M122.7 87h.6v1.1h-.6zM122.8 90.2h.9v1.7h-.9zM122.8 93h.1M122.9 87.1h.1M122.9 93h.1M122.9 93l-.1 .1h.1M122.9 83.7h.1M122.9 82.7h.1"/>
<path d="M123 92.7l.1 .1-.1 .6zM123 82.7h.1M123 83.7h.1M123 83.7l-.1 .1h.1M123 82.7l-.1 .1h.1M123 87v.1h-.1M123.2 90.5h.1M123.2 90.5l-.1 .1M123.2 90.5l.1 .1v-.1M123.3 88.8v.1M123.3 88.8l.1 .1M123.4 88.9h.1"/>
<path d="M123.4 88.9l-.1 .1h.1M123.4 92.5l-1.9 1.1M123.9 95.9h.6v1.1h-.6zM123.9 87.2h1.1v.6h-1.1zM124.1 83.4h3.1v3.1h-3.1zM124.1 96.1h.1M124.1 96v.1M124.1 96h.1M124.1 96l.1 .1v-.1M124.2 90.3h3.8l.5 .5v1.6h-4.3zM124.2 88.2h1.1v.6h-1.1zM124.9 93.9h1.8v1h-1.8z"/>
<path d="M124.9 87.4v.1M124.9 87.5h.1M124.9 87.5l-.1 .1h.1M125 82h1.1v.6h-1.1zM125.2 88.4v.1M125.2 88.5h.1M125.2 88.5l-.1 .1h.1M125.9 95.4h1.7v3h-1.7zM126 82.2v.1M126.1 82.3l-.1 .1h.1M126.1 82.3h.1M126.2 87.2h1.1v.6h-1.1z"/>
<path d="M126.3 94.3h.1M126.4 94.3h.1M126.4 94.3v.1M126.4 94.4l-.1 .1h.1M126.6 95.7v.2M126.6 95.7h.1M126.6 84.7h.2v.1l-.2 .3h.2M126.7 88.2h1.1v.6h-1.1zM126.9 95.7v.2l-.2-.2h-.1M127.1 87.4v.1M127.1 87.4l.1 .1M127.2 87.5h.1"/>
<path d="M127.2 87.5l-.1 .1h.1M127.6 91.1h.2l.1 .1-.3 .4h.3M127.6 88.4h.1M127.6 88.4v.1M127.7 88.4v.1M127.7 88.5h.1M127.7 88.5l-.1 .1h.1M127.9 86.5h.6v1.1h-.6zM127.9 84.7h.6v1.1h-.6zM128.1 83.5h1.1v.6h-1.1zM128.1 82.5h1.1v.6h-1.1zM128.1 86.6v.1"/>
<path d="M128.1 86.6h.1M128.1 84.8h.1M128.2 93.9h1.1v.6h-1.1zM128.2 84.8h.1M128.2 86.6l.1 .1v-.1M128.2 84.7v.1M128.2 84.7h.1M128.2 84.7l.1 .1v-.1M128.9 84.7h.6v1.1h-.6zM128.9 89.1h.6v1.1h-.6zM128.9 91h.6v1.1h-.6zM128.9 86.6h.6v1.1h-.6z"/>
<path d="M129 97.2h.6v1.1h-.6zM129.1 95.1h.6v1.1h-.6zM129.1 83.7h-.1M129.1 83.7h.1M129.1 82.7h-.1M129.1 82.7h.1M129.1 86.7h.1M129.1 84.8h.1M129.1 89.2h.1M129.1 91.1h.1M129.1 94.1h.1M129.1 83.7l-.1 .1h.1"/>
<path d="M129.1 82.7l-.1 .1h.1M129.1 86.6v.1M129.1 91v.1M129.1 89.1v.1M129.1 89.1h.1M129.1 84.7h.1M129.1 84.7v.1M129.1 86.6l.1 .1v-.1M129.1 84.7l.1 .1v-.1M129.1 89.1l.1 .1v-.1M129.1 91l.1 .1v-.1M129.2 94.1h.1"/>
<path d="M129.2 94.1l-.1 .1h.1M129.2 97.3h.1M129.3 97.3h-.1M129.3 97.3h.1M129.3 95.2h.1M129.3 97.2v.1M129.3 97.2h.1M129.3 97.2l.1 .1v-.1M129.3 95.1l.1 .1v-.1M132.3 84.8h4.1v4.1h-4.1zM132.4 83.4h1.1v.6h-1.1zM132.4 82.4h1.1v.6h-1.1z"/>
<path d="M132.6 81h1.7v.9h-1.7zM133.3 83.7h.1M133.4 82.6l-.1 .1M133.4 82.6v.1M133.4 82.7h.1M133.4 82.7l-.1 .1h.1M133.4 83.7l-.1 .1h.1M133.4 83.7h.1M133.7 90.1h1.1v.6h-1.1zM134 81.4h.1M134.1 81.4h.1M134.1 81.4l-.1 .2h.1"/>
<path d="M134.3 83.4h1.1v.6h-1.1zM134.3 82.4h1.1v.6h-1.1zM134.5 82.7h.1M134.6 82.7l-.1 .1M134.6 82.7h.1M134.6 90.3v.1M134.6 90.3l.1 .1M134.6 82.7v.1M134.7 90.4h.1M134.7 90.4l-.1 .1h.1M134.7 82.8h.1M134.7 82.7h.1"/>
<path d="M134.7 82.7v.1M134.8 82.7h.1M134.8 82.7v.1M134.8 82.8h.1M134.9 82.7h.1M134.9 82.7v.1M134.9 82.8h.1M135 82.7h.1M135 82.7v.1M135 82.8h.1M135.1 82.7h.1M135.2 82.7h.1"/>
<path d="M135.2 82.7h-.1M135.2 82.7l-.1 .1M135.2 82.8h-.2M135.2 83.7h.1M135.3 83.7h.1M135.3 83.7l-.1 .1h.1M135.6 89.6h1.1v.6h-1.1zM135.7 86.6h.1l.1 .1-.3 .4h.3M136.1 81.9h.9v1.7h-.9zM136.4 82.2h.1M136.4 82.1v.1M136.5 82.1h-.1"/>
<path d="M136.5 82.1h.1M136.5 82.1l.1 .1v-.1M136.5 89.8v.1M136.5 89.9h.1M136.6 89.9h.1M136.6 89.9l-.1 .1h.1M137.6 86.1h1.1v.6h-1.1zM137.6 87h1.1v.6h-1.1zM138.5 86.2l.1 .1M138.5 87.2h.1M138.6 86.3h.1M138.6 87.2h.1"/>
<path d="M138.6 87.2l-.1 .2h.1M138.6 86.3l-.1 .1h.1M150.2 97.7h2.6v2.6h-2.6zM150.2 89.3h1v1.8h-1zM150.3 95.4h1.1v.6h-1.1zM150.3 96.4h1.1v.6h-1.1zM151.1 95.6h.1h-.1M151.2 95.6v.1M151.2 96.6h.1M151.2 95.7h.1M151.2 95.8h.1M151.2 96.7l-.1 .1h.1"/>
<path d="M151.2 95.7v.1M151.2 96.6v.1M151.6 93.3h.6v1.1h-.6zM151.7 99h.2M152 95.6h.6v1.1h-.6zM152.1 90.5h1.7v.9h-1.7zM152.1 89h1.7v.9h-1.7zM152.2 83.7h.6v1.1h-.6zM152.2 81.8h.6v1.1h-.6zM152.4 82h.1M152.4 85.6h1.1v.6h-1.1zM152.5 81.9v.1"/>
<path d="M152.5 83.9v.1M153.3 90.8h.2l-.1 .3M153.3 85.9h.1M153.3 96.7h.9v1.7h-.9zM153.3 99.7h.9v1.7h-.9zM153.4 85.9v.1M153.4 89.3h.1M153.5 89.3h.1M153.5 89.3l-.1 .2M153.5 81.7h3.1v3.1h-3.1zM153.6 91.9h1.7v3h-1.7zM153.6 80.4h1.1v.6h-1.1z"/>
<path d="M153.9 100h-.2M153.9 100h.1M153.9 97.1l-.3-.1v.2M154.3 85.8h.6v1.1h-.6zM154.5 80.7h.1M154.5 80.6v.1M154.6 86h.1M154.6 85.9v.1M154.8 96.7h.9v1.7h-.9zM154.8 99.7h.9v1.7h-.9zM155.1 100v.1M155.1 90.5h1.7v.9h-1.7z"/>
<path d="M155.1 89h1.7v.9h-1.7zM155.1 97h.1M155.2 97h.1M155.2 100h.1M155.2 100h.2M155.2 97h.2M155.3 85.8h.6v1.1h-.6zM155.4 97h.1M155.4 100h.1M155.5 80.4h1.1v.6h-1.1zM155.5 86h.1M155.6 85.9v.1"/>
<path d="M155.9 83.3h.3M156.1 83.2v.3M156.3 80.7h.1M156.4 80.6v.1M156.4 90.8h.1M156.4 89.3l.1 .2M156.4 90.9h.1M156.5 90.8v.1M156.5 89.5h-.1M156.5 90.9l-.1 .1M156.5 90.9h-.1M157.7 81.8h.6v1.1h-.6z"/>
<path d="M157.7 83.7h.6v1.1h-.6zM158 85.6h1.1v.6h-1.1zM158 82l-.1-.1v.1M158 84l-.1-.1v.1M158 82h.1M158 83.9h.1M158 81.9v.1M158 81.9h.1M158.1 83.9h.1M158.1 81.9h.1M158.1 82h.1M158.3 91.5h.6v1.1h-.6z"/>
<path d="M158.3 95.2h.6v1.1h-.6zM158.8 85.8h.1v.1M158.9 85.9h.1M158.9 86h.1M158.9 85.9v.1M159.1 81.7h3.1v3.1h-3.1zM159.2 80.4h1.1v.6h-1.1zM159.7 89.9l1.9 1.1M159.7 91.7h7v7h-7zM159.9 85.8h.6v1.1h-.6zM160 80.6l.1 .1M160 80.7h.1"/>
<path d="M160.1 90.1l.1 .1-.1 .6zM160.1 90.1l1.2 .1h-1.2zM160.1 90.7l1.2 .1h-1.2zM160.1 80.7h.1M160.1 86h.1M160.2 86h-.1M160.2 85.9v.1M160.2 86h.1M160.3 90.5h.7M160.8 85.8h.6v1.1h-.6zM161 80.4h1.1v.6h-1.1zM161.1 86h-.1"/>
<path d="M161.1 85.9h.1M161.1 85.9v.1M161.2 90.1l.1 .1-.1 .6zM161.2 85.9v.1M161.2 86h.1M161.4 83h.3l-.1 .2M161.5 89.9l2 1.1M161.6 83.2l.1 .1-.1 .2M161.6 89.9l-1.9 1.1M161.9 80.6h.1l-.1 .1M161.9 90.1l.1 .1-.1 .6zM161.9 90.1l1.2 .1h-1.2z"/>
<path d="M161.9 90.7l1.2 .1h-1.2zM161.9 80.7h.1M162 80.7h-.1M162 80.7h.1M162.2 90.5h.6M163 90.1l.1 .1-.1 .6zM163.3 83.7h.6v1.1h-.6zM163.3 81.8h.6v1.1h-.6zM163.4 89.9l1.9 1.1M163.5 89.9l-2 1.1M163.5 83.9h.1M163.5 82h.1"/>
<path d="M163.5 81.9v.1M163.5 81.9h.1M163.5 85.6h1.1v.6h-1.1zM163.6 83.9v.1v-.1M163.6 81.9v.1v-.1M163.8 90.1l.1 .1-.1 .6zM163.8 90.1l1.2 .1h-1.2zM163.8 90.7l1.2 .1h-1.2zM164 90.5h.7M164.4 85.8h.1M164.5 85.8h.1M164.5 85.8v.1"/>
<path d="M164.5 85.9l-.1 .1h.1M164.5 85.9h.1M164.6 81.7h3.1v3.1h-3.1zM164.7 80.4h1.1v.6h-1.1zM164.9 90.1l.1 .1-.1 .6zM165.2 89.9l2 1.1M165.3 89.9l-1.9 1.1M165.4 85.8h.6v1.1h-.6zM165.6 80.6h.1M165.6 90.1l.1 .1v.6zM165.6 90.1l1.2 .1h-1.1zM165.6 90.7l1.2 .1h-1.1z"/>
<path d="M165.6 86h.1M165.7 80.6l-.1 .1h.1M165.7 80.6h.1M165.7 85.9h.1M165.7 85.9l.1 .1v-.1M165.9 90.5h.6M166.3 90.6h.2M166.4 85.8h.6v1.1h-.6zM166.6 80.4h1.1v.6h-1.1zM166.6 86h.1M166.6 85.9h.1M166.6 85.9v.1"/>
<path d="M166.6 85.9l.1 .1v-.1M166.7 90.1l.1 .1v.6zM167.2 83v.2l-.2 .3h.3M167.2 89.9l-2 1.1M167.4 80.6h.1M167.5 80.6h.1M167.5 80.6l-.1 .1h.1M167.6 92.7h.6v1.1h-.6zM167.7 91.5h1.1v.6h-1.1zM167.9 94.4h1.1v.6h-1.1zM167.9 95.6h1.1v.6h-1.1zM167.9 90h1.7v.9h-1.7z"/>
<path d="M168.8 83.7h.6v1.1h-.6zM168.8 81.8h.6v1.1h-.6zM169.1 85.6h1.1v.6h-1.1zM169.2 81.9v.1M169.2 83.9v.1M169.2 84h-.1M169.2 82h-.1M169.9 86h.1M170 85.8v.1M170 85.8v.2M170 85.8h.1M170.2 81.7h3.1v3.1h-3.1z"/>
<path d="M170.3 80.4h1.1v.6h-1.1zM170.6 94.8h.6v1.1h-.6zM170.6 96.7h.6v1.1h-.6zM171 97v.1M171 85.8h.6v1.1h-.6zM171.1 80.7h.1M171.2 80.6v.1M171.2 80.6h-.1M171.2 86h.1M171.3 85.9v.1M171.3 86h-.1M171.9 88.8h1.1v.6h-1.1z"/>
<path d="M171.9 85.8h.6v1.1h-.6zM172.1 90.2h8v8h-8zM172.1 80.4h1.1v.6h-1.1zM172.1 86h.2M172.1 86h.1M172.2 86h.1M172.3 85.9v.1M172.5 83.5h.3M172.5 89.2h.2M172.6 83.1l.1-.1v.5M173 80.7h.1M173 80.6v.1"/>
<path d="M173 80.6h.1M176.6 99.1h1.1v.6h-1.1zM181.1 97.9h.6v1.1h-.6zM181.3 95.7h1.1v.6h-1.1zM181.3 96.7h1.1v.6h-1.1zM181.3 89.7h1.1v.6h-1.1zM181.3 90.7h1.1v.6h-1.1zM181.3 91.7h1.1v.6h-1.1zM181.3 93.7h1.1v.6h-1.1zM181.3 94.7h1.1v.6h-1.1zM181.8 97.4l2 1.1M182 94.1h.1"/>
<path d="M182.2 97.6h.1l-.1 .7zM182.2 97.6h1.2l-1.2 .1zM182.2 98.2h1.2l-1.2 .1zM182.2 98.6h1.1v.6h-1.1zM182.6 97.9h.4M183.3 97.6h.1l-.1 .7zM183.4 93h3.2v2.5h-3.2zM183.8 97.4l-2 1.1M184.8 96.3h1.1v.6h-1.1zM185.3 87.5l2.8 2.8-1.4 1.4-2.9-2.8zM194.4 88.6l1.2 1.6M194.6 88.8l.8 .1h-.7z"/>
<path d="M194.6 88.8l.1 .1v1.1zM194.6 89.9l.8 .1h-.7zM194.7 88.9h.7v.2h-.7zM195 89.3v.4M195.3 88.8l.1 .1v1.1zM195.6 88.6l-1.2 1.6M195.9 83.7l26.6 10.6M196 84.2h.1l-.1 9.7zM196 84.2h26.5l-26.5 .1zM196 93.8h26.5l-26.5 .1zM204.3 95.9h5v22.3h-5zM222.4 84.2h.1v9.7z"/>
<path d="M222.5 83.7l-26.6 10.6M74.1 113.1h26.5v9.6h-26.5zM88.2 105.6h.5v3h-.5zM88.2 107.8l.5 .5M88.3 106.1a1 1 0 0 0-1 1 1 1 0 0 0 1 1M90.6 106.3h1.1v.6h-1.1zM90.6 109.3h1.1v.6h-1.1zM90.6 107.3h1.1v.6h-1.1zM90.6 108.3h1.1v.6h-1.1zM104 117.1h2.2v1.4h-2.2zM105 104.1h1.8v1h-1.8zM105.8 117.6h.2l-.1 .1 .1 .2h-.1"/>
<path d="M106.3 104.5h.2l-.1 .1M106.4 104.7h.1M106.4 104.6h.1M106.5 104.6v.1M106.5 104.7h-.1M106.8 116.8h1.1v.6h-1.1zM107.3 102.3l1.7 3.2M107.4 117.9h1.8v1h-1.8zM107.7 103h.1l-.1 1.8zM107.7 103h1l-1 .1zM107.7 104.7h1l-1 .1zM107.7 117h.1v.1"/>
<path d="M107.8 117.1h.1M107.8 117.2h.1M107.8 117.1v.1M108.1 103.3h-.1v.1M108.1 103.3l.1 .1M108.1 103.3h.1M108.2 103.2v1.4M108.6 103h.1l-.1 1.8zM108.7 116.8h1.1v.6h-1.1zM108.8 118.3h.1M108.9 118.3v.1M108.9 118.4l-.1 .1"/>
<path d="M108.9 118.4h.1M109 102.3l-1.7 3.2M109.6 117h.1v.1M109.7 117.1h.1M109.7 117.2h-.1M109.7 117.1v.1M111.4 104.6h.6v1.1h-.6zM111.4 106.5h.6v1.1h-.6zM111.7 104.7h-.1v.1M111.7 106.6h-.1v.1M111.7 104.7h.1M111.7 106.6h.1"/>
<path d="M111.8 104.7v.1M111.8 106.6h.1M112.7 106.4h.6v1.1h-.6zM112.9 106.6v-.1v.1M112.9 106.6h.1M112.9 106.5v.1M113 106.5h-.1M113 106.5h.1M113 106.5v.1M113 105h1.1v.6h-1.1zM113.8 103h.6v1.1h-.6zM113.9 106.4h.6v1.1h-.6z"/>
<path d="M113.9 105.2l.1 .1M114 105.4h.1M114 105.3h.1M114 105.3v.1M114 103.1v.1M114.1 103.1h.1M114.1 103.1h-.1M114.1 103.1v.1M114.2 106.6l-.1-.1v.1M114.2 106.6h.1M114.2 106.5v.1M114.2 106.5h.1"/>
<path d="M114.3 106.5v.1M115.1 103.1h.6v1.1h-.6zM115.3 105h1.1v.6h-1.1zM115.4 107.2h1.1v.6h-1.1zM115.4 103.2h-.1M115.4 103.2h.1M115.4 103.1h.1M115.4 103.1v.1M116.1 103h.6v1.1h-.6zM116.3 105.2h.1l-.1 .1M116.3 107.4h.1M116.3 107.5h.1"/>
<path d="M116.3 105.3h.1M116.3 103.1v.1M116.3 103.1h.1M116.3 105.3v.1M116.4 105.3h.1M116.4 105.3h-.1M116.4 103.1h.1M116.4 103.1h-.1M116.4 107.4v.1M116.4 107.5h-.1M116.4 103.1v.1M117.6 102.9h2.2l.5 .5v4.1h-3.2v-4.1z"/>
<path d="M118.9 103.9l-.1-.3h-.2v.2l-.2-.2v.3M119.9 110.7h1v1.8h-1zM120.1 113.3h1.1v.6h-1.1zM120.2 114.5h3v3.2l-.6 .6h-1.8l-.6-.6zM120.4 111h-.1v.1M120.4 111h.1M120.5 111h.1M120.5 111v.1M120.8 107.7h.9v1.7h-.9zM121 113.5h.1M121 113.6h.1M121 113.5l.1 .1"/>
<path d="M121.1 113.6h-.1M121.1 113.6h.1M121.1 105.8h1.8v1h-1.8zM121.2 108l-.1-.1v.2M121.2 108h.1M121.3 107.9l-.1 .1M121.3 107.9v.1M121.3 108h.1M121.5 113l1.9 1.1M121.7 111.1h.6v1.1h-.6zM121.9 113.2h.1l-.1 .7zM121.9 113.2l1.2 .1h-1.2z"/>
<path d="M121.9 113.8l1.2 .1h-1.2zM121.9 115.1l-.1-.2h-.2v.2l-.2-.2v.3M122 113.6h1M122 111.2l-.1 .1M122 111.2h.1M122 103h1.1v.6h-1.1zM122 104h1.1v.6h-1.1zM122.1 111.2h.1M122.4 109.1h1.1v.6h-1.1zM122.5 106.2h.1v.1M122.6 106.3h.1M122.6 106.4h-.1"/>
<path d="M122.6 106.3v.1M122.6 106.4h.1M122.7 107.5h.6v1.1h-.6zM122.8 110.7h.9v1.7h-.9zM122.8 113.5h.1M122.9 113.5h.1M122.9 113.5v.1M122.9 113.6h-.1M122.9 113.6h.1M122.9 104.2h.1v.1M122.9 103.2h.1v.1M123 104.3h.1"/>
<path d="M123 103.3h.1M123 107.6h-.1M123 113.2l.1 .1-.1 .6zM123 107.5v.1M123 104.3h-.1M123 103.3h-.1M123 107.6h.1M123.2 111h-.1v.1M123.2 111h.1M123.3 109.3v.1M123.3 111h.1M123.3 111v.1"/>
<path d="M123.3 109.5h.1M123.3 109.4h.1M123.4 109.4v.1M123.4 109.5h.1M123.4 113l-1.9 1.1M123.9 116.4h.6v1.1h-.6zM123.9 107.7h1.1v.6h-1.1zM124.1 103.9h3.1v3.1h-3.1zM124.1 116.5v.1M124.1 116.5h.1M124.2 110.8h3.8l.5 .5v1.6h-4.3zM124.2 116.5h.1"/>
<path d="M124.2 116.5v.1M124.2 108.7h1.1v.6h-1.1zM124.8 107.9l.1 .1M124.9 108.1h.1M124.9 114.4h1.8v1h-1.8zM124.9 108h.1M124.9 108v.1M125 102.5h1.1v.6h-1.1zM125.1 108.9l.1 .1M125.2 109.1h.1M125.2 109h.1M125.2 109v.1"/>
<path d="M125.9 115.9h1.7v3h-1.7zM126 102.7h.1l-.1 .1M126 102.8h.1M126 102.9h.1M126.1 102.8v.1M126.2 107.7h1.1v.6h-1.1zM126.3 114.8h.1l-.1 .1M126.3 114.9h.1M126.4 114.9h.1M126.4 115h-.1M126.4 114.9v.1M126.4 115h.1"/>
<path d="M126.6 105.2h.2l-.1 .2h.1v.2h-.2M126.7 108.7h1.1v.6h-1.1zM126.9 116.4v-.2h-.2v.1l-.2-.1v.2M127.1 107.9l.1 .1M127.2 108.1h-.1M127.2 108h.1M127.2 108.1h.1M127.2 108v.1M127.6 111.6h.3l-.2 .2h.1v.2l-.2 .1M127.6 108.9l.1 .1M127.6 109.1h.1M127.7 109h.1"/>
<path d="M127.7 109.1h.1M127.7 109v.1M127.9 107h.6v1.1h-.6zM127.9 105.2h.6v1.1h-.6zM128.1 104h1.1v.6h-1.1zM128.1 103h1.1v.6h-1.1zM128.2 114.4h1.1v.6h-1.1zM128.2 107.2l-.1-.1v.1M128.2 107.1v.1M128.2 107.1h.1M128.2 105.3h.1M128.2 105.3l-.1-.1v.1"/>
<path d="M128.2 105.2h.1M128.2 105.2v.1M128.3 107.1v.1M128.3 105.2v.1M128.3 105.3h.1M128.9 105.2h.6v1.1h-.6zM128.9 109.6h.6v1.1h-.6zM128.9 111.5h.6v1.1h-.6zM128.9 107.1h.6v1.1h-.6zM129 104.2l.1 .1M129 103.2l.1 .1M129 117.7h.6v1.1h-.6z"/>
<path d="M129 104.3h.1M129 103.3h.1M129.1 115.6h.6v1.1h-.6zM129.1 114.6h.1h-.1M129.1 104.3h.1M129.1 103.3h.1M129.1 114.6h.1M129.2 105.3l-.1-.1v.1M129.2 107.2l-.1-.1v.1M129.2 109.7l-.1-.1v.1M129.2 111.6l-.1-.1v.1M129.2 105.3h.1"/>
<path d="M129.2 107.2h.1M129.2 109.7h.1M129.2 111.6h.1M129.2 114.6v.1M129.2 114.7h-.1M129.2 114.7h.1M129.2 111.5v.1M129.2 109.6v.1M129.2 105.2v.1M129.2 107.1v.1M129.3 117.8h-.1M129.3 117.8h.1"/>
<path d="M129.3 115.7h.1M129.4 117.8h.1M129.4 115.7h.1M132.3 105.3h4.1v4.1h-4.1zM132.4 103.9h1.1v.6h-1.1zM132.4 102.9h1.1v.6h-1.1zM132.6 101.5h1.7v.9h-1.7zM133.3 104.1l.1 .1M133.3 103.1l.1 .1M133.3 103.3h.1M133.4 103.2h.1M133.4 104.2h.1"/>
<path d="M133.4 103.2v.1M133.4 104.2v.1M133.4 103.3h.1M133.4 104.3h-.1M133.4 104.3h.1M133.7 110.6h1.1v.6h-1.1zM134 101.9h.1v.1M134.1 102h.1M134.1 102.1h-.1M134.1 102v.1M134.3 103.9h1.1v.6h-1.1zM134.3 102.9h1.1v.6h-1.1z"/>
<path d="M134.5 103.2h.1M134.6 103.2l-.1 .1M134.6 103.2h.1M134.6 110.8l.1 .1M134.6 103.2v.1M134.7 110.9h.1M134.7 110.9v.1M134.7 111h-.1M134.7 103.3h.1M134.7 111h.1M134.7 103.2h.1M134.7 103.2v.1"/>
<path d="M134.8 103.2h.1M134.8 103.2v.1M134.8 103.3h.1M134.9 103.2h.1M134.9 103.2v.1M134.9 103.3h.1M135 103.2h.1M135 103.3h.1M135.1 103.2h.1M135.1 103.2v.1M135.1 103.3h.1M135.2 103.2h.1"/>
<path d="M135.2 103.3h-.2M135.2 104.1l.1 .1M135.3 104.2h.1M135.3 104.3h-.1M135.3 104.2v.1M135.3 104.3h.1M135.6 110.1h1.1v.6h-1.1zM135.6 107.1h.3l-.1 .1 .1 .1v.2h-.3M136.1 102.4h.9v1.7h-.9zM136.5 110.3v.1M136.5 102.6h-.1v.1M136.5 102.6h.1"/>
<path d="M136.5 110.4h.1M136.5 110.5h.1M136.6 110.5h-.1M136.6 110.4v.1M136.6 102.6h.1M136.6 102.6v.1M137.6 107.5h1.1v.6h-1.1zM137.6 106.6h1.1v.6h-1.1zM138.5 107.7h.1l-.1 .1M138.5 106.7h.1l-.1 .1M138.6 106.8h.1M138.6 107.8h.1"/>
<path d="M138.6 106.8v.1M138.6 107.9h.1M138.6 106.9h.1M138.6 107.8v.1M150.2 105.3h2.7v3.4h-2.7zM150.3 116.6h1.1v.6h-1.1zM150.3 114.6h1.1v.6h-1.1zM150.3 115.6h1.1v.6h-1.1zM150.4 101.1h1.1v.6h-1.1zM150.5 118h1v1.8h-1zM150.6 103.4h1.8v1h-1.8zM150.9 118.4h.2"/>
<path d="M151.1 109.7h1.7v.9h-1.7zM151.1 111.2h1.7v.9h-1.7zM151.1 115h.1M151.1 101.3h.1v.1M151.1 116.8h.1M151.1 115.8h.1M151.1 116.8v.1M151.1 116.9h.1M151.2 115.8h.1M151.2 115.8l-.2 .2h.2M151.2 101.4h.1M151.2 101.5h.1"/>
<path d="M151.2 101.4v.1M151.4 112.6h1.3v1.7h-1.3zM151.9 103.7h.1M152 103.9v.1M152 115.1h1.4v2.2h-1.4zM152 104h.1M152.1 110.3h.2M152.2 113.1v.1M152.4 111.5v.2M152.4 111.6v.1M152.4 111.7v.1M152.4 111.6h.1"/>
<path d="M152.5 115.5h.3M152.8 119.7h2.6v2.6h-2.6zM153.2 118.3h1.1v.6h-1.1zM153.5 104.5h1.4v2.2h-1.4zM153.6 100v.1M153.6 102.3h1.8v1h-1.8zM154 113.2h2.7v3.4h-2.7zM154 104.9h.1M154 118.5h.1v.2M154.1 104.9h.2M154.2 117.4h1.1v.6h-1.1zM154.3 109.7h1.7v.9h-1.7z"/>
<path d="M154.3 111.2h1.7v.9h-1.7zM154.3 107.6h1.3v1.7h-1.3zM155 117.6h.1M155 117.6l.1 .1M155.1 117.7h.1M155.1 117.8h-.1M155.1 117.8h.1M155.1 117.7v.1M155.5 110h.2l-.2 .3M155.5 104.7h1.1v.6h-1.1zM155.5 106.6h1.1v.6h-1.1zM155.5 103.8h1.1v.6h-1.1z"/>
<path d="M155.5 105.7h1.1v.6h-1.1zM156 118.6h.9v1.7h-.9zM156.4 119l-.2-.1v.2M156.4 103.9h.1M156.4 118.9v.1M156.4 104.9h.1M156.4 104h.1M156.4 106.8v.2M156.4 104.1h.1M156.4 118.9h.1M156.4 104.9v.1M156.4 105h.1"/>
<path d="M156.4 104v.1M156.4 105v.1M156.5 118.9h.1M156.5 118.9v.1M157.5 118.6h.9v1.7h-.9zM157.9 118.9v.2M162.1 119.7h.6v1.1h-.6zM162.3 119.9v.1M162.4 119.9h.1M162.5 119.9h.1M163.5 109.5h15v15h-15zM170.3 107.4h.6v1.1h-.6z"/>
<path d="M170.5 107.6h-.1M170.6 107.6v.1l-.1-.1M171 106.9l1 2M171.2 107.3l.7 .1h-.7zM171.2 107.3l.1 .1-.1 1.1zM171.2 108.4l.7 .1h-.7zM171.5 107.6v.6M171.8 107.3l.1 .1-.1 1.1zM172 106.9l-1 2M172.2 107.4h.6v1.1h-.6zM172.5 107.7v.1M173.1 107.4h.6v1.1h-.6z"/>
<path d="M173.8 106.9l1.1 2M174 107.3l.7 .1h-.7zM174 107.3l.1 .1v1.1zM174 108.4l.7 .1h-.6zM174.3 107.6v.6M174.6 107.3l.1 .1v1.1zM174.9 106.9l-1.1 2M175 107.4h.6v1.1h-.6zM175.7 106.9l1.1 2M175.9 107.3l.7 .1h-.7zM175.9 107.3l.1 .1v1.1zM175.9 108.4l.7 .1h-.6z"/>
<path d="M176.2 107.6v.6M176.5 107.3l.1 .1v1.1zM176.8 106.9l-1.1 2M176.9 107.4h.6v1.1h-.6zM177.6 106.9l1.1 2M177.8 107.3l.7 .1h-.7zM177.8 107.3l.1 .1v1.1zM177.8 108.4l.7 .1h-.6zM178.1 107.6v.6M178.4 107.3l.1 .1v1.1zM178.7 106.9l-1.1 2M179.8 107.2h2v1.6h-2z"/>
<path d="M180.1 111.9h2.7v3.4h-2.7zM180.7 110.1h1.8v1h-1.8zM181 117.9h1.7v.9h-1.7zM181 116.4h1.7v.9h-1.7zM181.4 119.3h1.3v1.7h-1.3zM182.2 107.4h.6v1.1h-.6zM182.2 116.7h.1M182.3 116.8v.2M182.4 107.6h.1M183.4 111.2h1.4v2.2h-1.4zM184.1 119.9h2.7v3.4h-2.7zM184.2 117.9h1.7v.9h-1.7z"/>
<path d="M184.2 116.4h1.7v.9h-1.7zM184.3 114.2h1.3v1.7h-1.3zM185.4 113.3h1.1v.6h-1.1zM185.4 112.4h1.1v.6h-1.1zM185.4 111.4h1.1v.6h-1.1zM195.9 119.8l26.6 10.6M222.5 119.8l-26.6 10.6M74.1 134.7h26.5v9.6h-26.5zM88.1 126.1h3.5v5.3h-3.5zM104 137.6h2.2v1.4h-2.2zM105 124.6h1.8v1h-1.8zM105.9 138.1v.2h.1"/>
<path d="M106 138.2v.2M106.4 125v.2h.1M106.4 125.1v.1M106.8 137.3h1.1v.6h-1.1zM107.3 122.8l1.7 3.2M107.4 138.4h1.8v1h-1.8zM107.7 123.5h.1l-.1 1.8zM107.7 123.5h1l-1 .1zM107.7 125.2h1l-1 .1zM107.8 137.5v.1M107.8 137.6v.1M108.1 123.8h.1"/>
<path d="M108.1 123.7v1.4M108.2 123.8v.1l-.2-.1M108.6 123.5h.1l-.1 1.8zM108.7 137.3h1.1v.6h-1.1zM108.8 138.7v.2h.1M108.9 138.8v.2M109 122.8l-1.7 3.2M109.7 137.5l-.1 .1h.1M109.7 137.6v.1M111.4 125.1h.6v1.1h-.6zM111.4 127h.6v1.1h-.6zM111.7 125.2h.1"/>
<path d="M111.7 127.1h.1M111.7 125.2v.1l-.1-.1M111.7 127.1v.1l-.1-.1M112.7 126.9h.6v1.1h-.6zM112.9 127h.1M113 127v.1h-.1M113 125.5h1.1v.6h-1.1zM113.8 123.5h.6v1.1h-.6zM113.9 126.9h.6v1.1h-.6zM114 125.7v.1M114 123.6h.1M114 125.8v.1"/>
<path d="M114.1 123.6v.1h-.1M114.2 127h.1M114.2 127v.1h-.1M115.1 123.6h.6v1.1h-.6zM115.3 125.5h1.1v.6h-1.1zM115.3 123.7h.1M115.4 127.7h1.1v.6h-1.1zM115.4 123.6v.1h-.1M116.1 123.5h.6v1.1h-.6zM116.3 125.7v.1h.1M116.3 127.9v.1h.1M116.3 123.6h.1"/>
<path d="M116.3 125.8v.1M116.3 127.9v.1M116.4 123.6v.1h-.1M117.6 123.4h2.2l.5 .5v4.1h-3.2v-4.1zM118.5 124.2h.4M118.7 124.1v.3l-.3-.1M119.9 131.2h1v1.8h-1zM120.1 133.8h1.1v.6h-1.1zM120.2 135h3v3.2l-.6 .6h-1.8l-.6-.6zM120.4 131.5h.1M120.4 131.5v.1l-.1-.1M120.8 128.2h.9v1.7h-.9z"/>
<path d="M121 134v.1h.1M121 134v.1M121.1 126.3h1.8v1h-1.8zM121.2 128.5h.1M121.2 128.4v.2l-.1-.1M121.5 133.5l1.9 1.1M121.5 135.4h.4M121.7 131.6h.6v1.1h-.6zM121.7 135.4v.3l-.3-.1M121.9 133.7h.1l-.1 .7zM121.9 133.7l1.2 .1h-1.2zM121.9 134.3l1.2 .1h-1.2z"/>
<path d="M122 134.1h1M122 131.7h.1M122 123.5h1.1v.6h-1.1zM122 124.5h1.1v.6h-1.1zM122 131.7v.1l-.1-.1M122.4 129.6h1.1v.6h-1.1zM122.5 126.7v.1h.1M122.6 126.8v.1M122.7 128h.6v1.1h-.6zM122.8 131.2h.9v1.7h-.9zM122.9 134l-.1 .1h.1M122.9 134v.1"/>
<path d="M122.9 128.1h.1M123 123.7l-.1 .1h.1M123 124.7l-.1 .1h.1M123 133.7l.1 .1-.1 .6zM123 128v.1h-.1M123 123.7v.1M123 124.7v.1M123.2 131.5h.1M123.2 131.5v.1l-.1-.1M123.3 129.8v.1h.1M123.3 129.9v.1M123.4 133.5l-1.9 1.1"/>
<path d="M123.9 136.9h.6v1.1h-.6zM123.9 128.2h1.1v.6h-1.1zM124.1 124.4h3.1v3.1h-3.1zM124.1 137h.1M124.2 137v.1h-.1M124.2 131.3h3.8l.5 .5v1.6h-4.3zM124.2 129.2h1.1v.6h-1.1zM124.9 134.9h1.8v1h-1.8zM124.9 128.4v.1M124.9 128.5v.1M125 123h1.1v.6h-1.1zM125.2 129.4v.1"/>
<path d="M125.2 129.5v.1M125.9 136.4h1.7v3h-1.7zM126 123.2v.1h.1M126 123.3v.1M126.2 128.2h1.1v.6h-1.1zM126.3 135.3v.1h.1M126.4 135.4v.1M126.7 136.7h.2M126.7 129.2h1.1v.6h-1.1zM126.7 125.7l-.1 .3h.3M126.8 136.7v.2l-.3-.1M126.8 125.8v.3"/>
<path d="M127.2 128.4l-.1 .1h.1M127.2 128.5v.1M127.7 129.4l-.1 .1h.1M127.7 129.5v.1M127.7 132.1l-.1 .3h.3M127.8 132.2v.4M127.9 127.5h.6v1.1h-.6zM127.9 125.7h.6v1.1h-.6zM128.1 124.5h1.1v.6h-1.1zM128.1 123.5h1.1v.6h-1.1zM128.2 134.9h1.1v.6h-1.1zM128.2 127.6h.1"/>
<path d="M128.2 125.8h.1M128.2 127.6v.1h-.1M128.2 125.7v.1h-.1M128.9 125.7h.6v1.1h-.6zM128.9 130.1h.6v1.1h-.6zM128.9 132h.6v1.1h-.6zM128.9 127.6h.6v1.1h-.6zM129 138.2h.6v1.1h-.6zM129.1 136.1h.6v1.1h-.6zM129.1 124.7l-.1 .1h.1M129.1 123.7l-.1 .1h.1M129.1 124.7v.1"/>
<path d="M129.1 123.7v.1M129.1 135.1v.1h.1M129.1 125.8h.1M129.1 127.7h.1M129.1 130.2h.1M129.1 132.1h.1M129.1 135.1v.1M129.2 127.6v.1h-.1M129.2 125.7v.1h-.1M129.2 130.1v.1h-.1M129.2 132v.1h-.1M129.3 138.3h.1"/>
<path d="M129.3 136.2h.1M129.3 138.2v.1h-.1M129.4 136.1v.1h-.1M132.3 125.8h4.1v4.1h-4.1zM132.4 123.4h1.1v.6h-1.1zM132.4 124.4h1.1v.6h-1.1zM132.6 122h1.7v.9h-1.7zM133.3 123.6v.1h.1M133.3 124.6v.1h.1M133.4 123.7v.1M133.4 124.7v.1M133.7 131.1h1.1v.6h-1.1z"/>
<path d="M134 122.4v.1h.1M134.1 122.4v.2M134.3 124.4h1.1v.6h-1.1zM134.3 123.4h1.1v.6h-1.1zM134.5 123.7h.1M134.6 123.7l-.1 .1M134.6 123.7h.1M134.6 123.7v.1M134.6 131.3v.1h.1M134.7 131.4v.1M134.7 123.8h.1M134.7 123.7v.1"/>
<path d="M134.7 123.7h.1M134.8 123.7h.1M134.8 123.7v.1M134.8 123.8h.1M134.9 123.7h.1M134.9 123.7v.1M134.9 123.8h.1M135 123.7h.1M135 123.7v.1M135 123.8h.1M135.2 123.7h.1M135.2 123.7v.1"/>
<path d="M135.2 124.6v.1h.1M135.3 124.7v.1M135.6 130.6h1.1v.6h-1.1zM135.8 127.5l-.2 .4h.3M135.9 127.7v.4M136.1 122.9h.9v1.7h-.9zM136.5 123.1h.1M136.5 130.8v.1h.1M136.5 130.9v.1M136.6 123.1v.1h-.2M137.6 127.1h1.1v.6h-1.1zM137.6 128h1.1v.6h-1.1z"/>
<path d="M138.5 127.4h.1M138.5 128.3h.1M150.3 122.4l2.9 2.8-1.5 1.4-2.8-2.8zM153.2 123h1.1v.6h-1.1zM154 123.2h.1M154.1 123.3v.1M154.1 123.4h.1M156 121.6h.9v1.7h-.9zM156.3 124.2h1.8v1h-1.8zM156.5 121.9v.2l-.1-.2-.2 .1M157.4 127.3l1.1 2M157.5 121.6h.9v1.7h-.9z"/>
<path d="M157.5 124.5h.2l-.1 .2M157.6 124.7l.1 .1M157.6 127.7h.1v1.2zM157.6 127.7h.7l-.6 .1zM157.6 128.8h.7l-.6 .1zM157.6 124.8h.1M157.7 124.8h-.1M158 128v.6M158 121.9v.2M158 122h-.2M158.2 127.7h.1v1.2zM158.4 127.3l1.1 2"/>
<path d="M158.5 127.3l-1.1 2M158.6 127.7h.1v1.2zM158.6 127.7h.7l-.6 .1zM158.6 128.8h.7l-.6 .1zM159 128v.6M159.2 127.7h.1v1.2zM159.4 127.3l1.1 2M159.5 127.3l-1.1 2M159.6 127.7h.1v1.2zM159.6 127.7h.7l-.6 .1zM159.6 128.8h.7l-.6 .1zM160 128v.6"/>
<path d="M160.2 127.7h.1v1.2zM160.4 127.3l1.1 2M160.5 127.3l-1.1 2M160.6 127.7h.1v1.2zM160.6 127.7h.7l-.6 .1zM160.6 128.8h.7l-.6 .1zM161 128v.6M161.2 127.7h.1v1.2zM161.4 127.3l1.1 2M161.5 127.3l-1.1 2M161.6 127.7h.1v1.2zM161.6 127.7h.7l-.6 .1z"/>
<path d="M161.6 128.8h.7l-.6 .1zM162 128v.6M162.2 127.7h.1v1.2zM162.4 127.3l1.1 2M162.5 127.3l-1.1 2M162.6 127.7h.1v1.2zM162.6 127.7h.7l-.6 .1zM162.6 128.8h.7l-.6 .1zM163 128v.6M163.2 127.7h.1v1.2zM163.4 127.3l1.1 2M163.5 127.3l-1.1 2"/>
<path d="M163.6 127.7h.1v1.2zM163.6 127.7h.7l-.6 .1zM163.6 128.8h.7l-.6 .1zM164 128v.6M164.2 127.7h.1v1.2zM164.4 127.3l1.1 2M164.5 127.3l-1.1 2M164.6 127.7h.1v1.2zM164.6 127.7h.7l-.6 .1zM164.6 128.8h.7l-.6 .1zM165 128v.6M165.2 127.7h.1v1.2z"/>
<path d="M165.4 127.3l1.1 2M165.5 127.3l-1.1 2M165.6 127.7h.1v1.2zM165.6 127.7h.7l-.6 .1zM165.6 128.8h.7l-.6 .1zM166 128v.6M166.1 128v.1M166.2 127.7h.1v1.2zM166.4 127.3l1.1 2M166.5 127.3l-1.1 2M166.6 127.7h.1v1.2zM166.6 127.7h.7l-.6 .1z"/>
<path d="M166.6 128.8h.7l-.6 .1zM167 128v.6M167.2 127.7h.1v1.2zM167.5 127.3l-1.1 2M167.7 127.7h.6v1.1h-.6zM168.6 127.7h.6v1.1h-.6zM169.6 127.7h.6v1.1h-.6zM170.5 127.7h.6v1.1h-.6zM171.5 127.7h.6v1.1h-.6zM172.4 127.7h.6v1.1h-.6zM173.4 127.7h.6v1.1h-.6zM174.3 127.7h.6v1.1h-.6z"/>
<path d="M175.8 127.7h.6v1.1h-.6zM180.1 121.9h1.4v2.2h-1.4zM181 122.4l-.4-.1v.2M182.1 121.9h1.4v2.2h-1.4zM182.6 122.3v.1M182.7 122.4l.1-.1 .2 .1M184.4 124.2h1.8v1h-1.8zM185.7 124.5h.1M185.7 124.6h.1M185.8 124.8h-.1M185.8 124.6v.1M185.8 124.8h.1"/>
<path d="M185.8 124.7v.1M196 120.3h.1l-.1 9.7zM196 120.3h26.5l-26.5 .1zM196 129.9h26.5l-26.5 .1zM198.1 138.2l12.3 10.4M198.3 138.5v9.8zM198.3 138.5h11.9zM204.6 130.7l6 7.2M204.8 131.6l3.7 .1h-3.7zM204.8 131.6l.1 .1-.1 5.3zM204.8 136.9l3.7 .1h-3.7zM206.9 133.6v1.4"/>
<path d="M208.4 131.6l.1 .1-.1 5.3zM210.1 138.5l.1 9.8zM210.4 138.2l-12.3 10.4M210.6 130.7l-6 7.2M222.4 120.3h.1v9.7zM87 150.3h15M91 150.3a.5 .5 0 0 0-.5 .5 .5 .5 0 0 0 .5 .5h7a.5 .5 0 0 0 .5-.5 .5 .5 0 0 0-.5-.5M102 150.3v-8.2h18.4v8.2h8M102.5 142.1a.5 .5 0 0 0-.5 .5M108.9 142.1a.5 .5 0 0 1 .5 .5 .5 .5 0 0 1-.5 .5h-5.4a.5 .5 0 0 0-.5 .5v6.7a.5 .5 0 0 1-.5 .5 .5 .5 0 0 1-.5-.5M113.4 142.1a.5 .5 0 0 0-.5 .5 .5 .5 0 0 0 .6 .5h5.4a.5 .5 0 0 1 .5 .5v6.7a.5 .5 0 0 0 .5 .5 .5 .5 0 0 0 .5-.5v-7.7a.5 .5 0 0 0-.5-.5M169 142.1h40.5"/>
<path d="M173.4 142.1a.5 .5 0 0 0-.5 .5 .5 .5 0 0 0 .5 .5h6.5a.5 .5 0 0 0 .5-.5 .5 .5 0 0 0-.5-.5M184.4 142.1a.5 .5 0 0 0-.5 .5 .5 .5 0 0 0 .5 .5h6.5a.5 .5 0 0 0 .5-.5 .5 .5 0 0 0-.5-.5M195.5 142.1a.5 .5 0 0 0-.5 .5 .5 .5 0 0 0 .5 .5h6.5a.5 .5 0 0 0 .5-.5 .5 .5 0 0 0-.5-.5M198.3 148.3h11.9z"/>
</g>
<g fill="none" stroke="#000" stroke-width=".2">
<path d="M74.8 57.1h.3M75.1 56.7h-.3v1h.4M119.9 59.3l.3-.3v1M95 75h.5M95 74.3l.2-.3v1M107.1 66.9v.6M107.1 67.2h-1l.3 .3M115.8 69.5v.6M115.8 69.8h-1l.3 .3M119.9 60h.6M120 79.6l.3-.1 .2 .1v.2l-.6 .7h.6M95 95.7h.3l.2 .1v.2l-.6 .7h.6"/>
<path d="M107.1 87.4v.7l-.7-.7-.2 .1-.1 .1v.4M115.8 90v.6l-.7-.6h-.2l-.1 .2v.3M203 89h2M94.9 117.3h.6l-.3 .4 .3 .1v.3l-.2 .2h-.2M107.1 108.4v-.3l-.2-.2-.4 .1v.3l-.4-.4v.7M115.8 111v-.3l-.2-.2h-.3l-.1 .3-.4-.3v.6M119.9 100h.6l-.3 .4 .3 .1v.3l-.2 .2h-.3M95.2 138.9l-.2 .7h.6M95.4 139.3v.7M106.4 128.5h.7M106.7 128.4v.6l-.7-.2M115.1 131.1h.7"/>
<path d="M115.4 130.9v.7l-.7-.3M120.2 120.5l-.3 .7h.7M120.4 120.8v.7M203 125.1h2M202.2 142v2.9M202.7 142.3v.5M211.6 142h.8M216.4 142.4v-1l.6 1M220 141.4h.4l.1 .1M220 141.9h.4M220.4 141.9h.1M220.5 142.4h-.5"/>
<path d="M220.5 141.8l-.1 .1"/>
<circle cx="202.8" cy="115.8" r=".1"/>
</g>
<path d="M169.9 105h1.2" fill="none" stroke="#000" stroke-width=".4"/>
<g fill="none" stroke="#000" stroke-width=".25">
<path d="M101.4 60.5h29.3v18.5h-29.3zM103.4 64.7h6.5v10.6h-6.5zM103.4 65.5h6.5M112.1 67.3h6.5v10.6h-6.5zM112.1 68.1h6.5M101.4 81h29.3v18.5h-29.3zM103.4 85.2h6.5v10.6h-6.5zM103.4 86h6.5M112.1 87.8h6.5v10.6h-6.5zM112.1 88.6h6.5M101.4 101.5h29.3v18.5h-29.3zM103.4 105.7h6.5v10.6h-6.5z"/>
<path d="M103.4 106.5h6.5M112.1 108.3h6.5v10.6h-6.5zM112.1 109.1h6.5M101.4 122h29.3v18.5h-29.3zM103.4 126.2h6.5v10.6h-6.5zM103.4 127h6.5M112.1 128.8h6.5v10.6h-6.5zM112.1 129.6h6.5"/>
</g>
<g fill="#000">
<path d="M124.1 62.9h.7l-.7 .7zM125.9 74.9h.7l-.7 .7zM134.7 75.2h.7l-.7 .7zM135.7 64.3h.7v.7zM154.2 62.5h1.2v1.2zM156.1 66.3l.7 .7h-.7zM163.6 66.3l.7-.7v.7zM168.7 64.3h.7v.7zM174.2 63.4h.7l-.7 .7zM182.9 68.6l.7 .7h-.7zM183.5 60.8l1.1 1.1h-1.1zM124.1 83.4h.7l-.7 .7z"/>
<path d="M125.9 95.4h.7l-.7 .7zM135.7 84.8h.7v.7zM152.1 97.7h.7v.7zM153.6 91.9h.7l-.7 .7zM155.9 81.7h.7v.7zM159.7 91.7h1.1l-1.1 1.1zM161.5 81.7h.7v.7zM167 81.7h.7v.7zM172.6 81.7h.7v.7zM172.1 97l1.3 1.2h-1.3zM185.9 93h.7v.7zM124.1 103.9h.7l-.7 .7z"/>
<path d="M125.9 115.9h.7l-.7 .7zM135.7 105.3h.7v.7zM152.2 114.3l.5-.5v.5zM154.3 107.6h.5l-.5 .5zM181.1 107.2h.7v.7zM184.3 114.2h.5l-.5 .5zM124.1 124.4h.7l-.7 .7zM125.9 136.4h.7l-.7 .7zM135.7 125.8h.7v.7zM154.7 119.7h.7v.7zM163.5 123l1.5 1.5h-1.5zM182.2 121l.5-.5v.5z"/>
</g>
<g fill="none" stroke="#000" stroke-width=".15">
<path d="M187 83.6l-5 5h-32.2v32.2l-4.8 4.7M192 88.6l-4.8 4.8v32.2h-32.2l-5 4.9"/>
<circle cx="189.4" cy="86.2" r="3.5"/>
<circle cx="147.6" cy="127.9" r="3.5"/>
</g>
<use href="#words"/>
</svg>
